VERSION 5.8 ;
BUSBITCHARS "[]" ;
DIVIDERCHAR "/" ;
UNITS
    DATABASE MICRONS 1000 ;
END UNITS

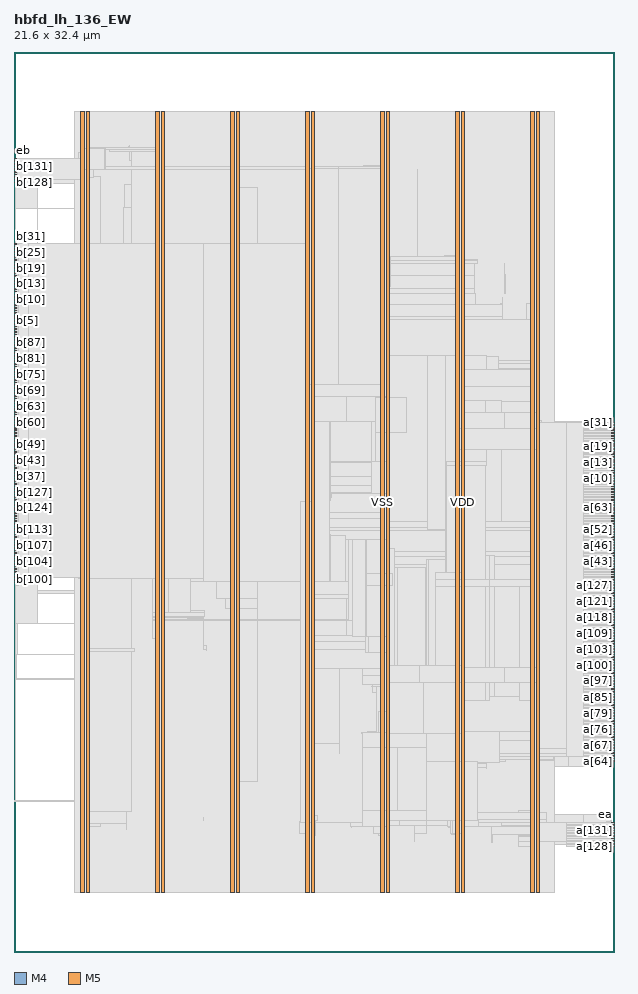
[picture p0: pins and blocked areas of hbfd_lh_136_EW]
MACRO hbfd_lh_136_EW
  FOREIGN hbfd_lh_136_EW 0 0 ;
  CLASS BLOCK ;
  SIZE 21.6 BY 32.4 ;
  PIN a[0]
    DIRECTION INPUT ;
    USE SIGNAL ;
    PORT
      LAYER M4 ;
        RECT  21.516 16.08 21.6 16.104 ;
    END
  END a[0]
  PIN a[100]
    DIRECTION INPUT ;
    USE SIGNAL ;
    PORT
      LAYER M4 ;
        RECT  21.516 10.32 21.6 10.344 ;
    END
  END a[100]
  PIN a[101]
    DIRECTION INPUT ;
    USE SIGNAL ;
    PORT
      LAYER M4 ;
        RECT  21.516 10.416 21.6 10.44 ;
    END
  END a[101]
  PIN a[102]
    DIRECTION INPUT ;
    USE SIGNAL ;
    PORT
      LAYER M4 ;
        RECT  21.516 10.512 21.6 10.536 ;
    END
  END a[102]
  PIN a[103]
    DIRECTION INPUT ;
    USE SIGNAL ;
    PORT
      LAYER M4 ;
        RECT  21.516 10.608 21.6 10.632 ;
    END
  END a[103]
  PIN a[104]
    DIRECTION INPUT ;
    USE SIGNAL ;
    PORT
      LAYER M4 ;
        RECT  21.516 10.704 21.6 10.728 ;
    END
  END a[104]
  PIN a[105]
    DIRECTION INPUT ;
    USE SIGNAL ;
    PORT
      LAYER M4 ;
        RECT  21.516 10.8 21.6 10.824 ;
    END
  END a[105]
  PIN a[106]
    DIRECTION INPUT ;
    USE SIGNAL ;
    PORT
      LAYER M4 ;
        RECT  21.516 10.896 21.6 10.92 ;
    END
  END a[106]
  PIN a[107]
    DIRECTION INPUT ;
    USE SIGNAL ;
    PORT
      LAYER M4 ;
        RECT  21.516 10.992 21.6 11.016 ;
    END
  END a[107]
  PIN a[108]
    DIRECTION INPUT ;
    USE SIGNAL ;
    PORT
      LAYER M4 ;
        RECT  21.516 11.088 21.6 11.112 ;
    END
  END a[108]
  PIN a[109]
    DIRECTION INPUT ;
    USE SIGNAL ;
    PORT
      LAYER M4 ;
        RECT  21.516 11.184 21.6 11.208 ;
    END
  END a[109]
  PIN a[10]
    DIRECTION INPUT ;
    USE SIGNAL ;
    PORT
      LAYER M4 ;
        RECT  21.516 17.04 21.6 17.064 ;
    END
  END a[10]
  PIN a[110]
    DIRECTION INPUT ;
    USE SIGNAL ;
    PORT
      LAYER M4 ;
        RECT  21.516 11.28 21.6 11.304 ;
    END
  END a[110]
  PIN a[111]
    DIRECTION INPUT ;
    USE SIGNAL ;
    PORT
      LAYER M4 ;
        RECT  21.516 11.376 21.6 11.4 ;
    END
  END a[111]
  PIN a[112]
    DIRECTION INPUT ;
    USE SIGNAL ;
    PORT
      LAYER M4 ;
        RECT  21.516 11.472 21.6 11.496 ;
    END
  END a[112]
  PIN a[113]
    DIRECTION INPUT ;
    USE SIGNAL ;
    PORT
      LAYER M4 ;
        RECT  21.516 11.568 21.6 11.592 ;
    END
  END a[113]
  PIN a[114]
    DIRECTION INPUT ;
    USE SIGNAL ;
    PORT
      LAYER M4 ;
        RECT  21.516 11.664 21.6 11.688 ;
    END
  END a[114]
  PIN a[115]
    DIRECTION INPUT ;
    USE SIGNAL ;
    PORT
      LAYER M4 ;
        RECT  21.516 11.76 21.6 11.784 ;
    END
  END a[115]
  PIN a[116]
    DIRECTION INPUT ;
    USE SIGNAL ;
    PORT
      LAYER M4 ;
        RECT  21.516 11.856 21.6 11.88 ;
    END
  END a[116]
  PIN a[117]
    DIRECTION INPUT ;
    USE SIGNAL ;
    PORT
      LAYER M4 ;
        RECT  21.516 11.952 21.6 11.976 ;
    END
  END a[117]
  PIN a[118]
    DIRECTION INPUT ;
    USE SIGNAL ;
    PORT
      LAYER M4 ;
        RECT  21.516 12.048 21.6 12.072 ;
    END
  END a[118]
  PIN a[119]
    DIRECTION INPUT ;
    USE SIGNAL ;
    PORT
      LAYER M4 ;
        RECT  21.516 12.144 21.6 12.168 ;
    END
  END a[119]
  PIN a[11]
    DIRECTION INPUT ;
    USE SIGNAL ;
    PORT
      LAYER M4 ;
        RECT  21.516 17.136 21.6 17.16 ;
    END
  END a[11]
  PIN a[120]
    DIRECTION INPUT ;
    USE SIGNAL ;
    PORT
      LAYER M4 ;
        RECT  21.516 12.24 21.6 12.264 ;
    END
  END a[120]
  PIN a[121]
    DIRECTION INPUT ;
    USE SIGNAL ;
    PORT
      LAYER M4 ;
        RECT  21.516 12.336 21.6 12.36 ;
    END
  END a[121]
  PIN a[122]
    DIRECTION INPUT ;
    USE SIGNAL ;
    PORT
      LAYER M4 ;
        RECT  21.516 12.432 21.6 12.456 ;
    END
  END a[122]
  PIN a[123]
    DIRECTION INPUT ;
    USE SIGNAL ;
    PORT
      LAYER M4 ;
        RECT  21.516 12.528 21.6 12.552 ;
    END
  END a[123]
  PIN a[124]
    DIRECTION INPUT ;
    USE SIGNAL ;
    PORT
      LAYER M4 ;
        RECT  21.516 12.624 21.6 12.648 ;
    END
  END a[124]
  PIN a[125]
    DIRECTION INPUT ;
    USE SIGNAL ;
    PORT
      LAYER M4 ;
        RECT  21.516 12.72 21.6 12.744 ;
    END
  END a[125]
  PIN a[126]
    DIRECTION INPUT ;
    USE SIGNAL ;
    PORT
      LAYER M4 ;
        RECT  21.516 12.816 21.6 12.84 ;
    END
  END a[126]
  PIN a[127]
    DIRECTION INPUT ;
    USE SIGNAL ;
    PORT
      LAYER M4 ;
        RECT  21.516 12.912 21.6 12.936 ;
    END
  END a[127]
  PIN a[128]
    DIRECTION INPUT ;
    USE SIGNAL ;
    PORT
      LAYER M4 ;
        RECT  21.516 3.792 21.6 3.816 ;
    END
  END a[128]
  PIN a[129]
    DIRECTION INPUT ;
    USE SIGNAL ;
    PORT
      LAYER M4 ;
        RECT  21.516 3.888 21.6 3.912 ;
    END
  END a[129]
  PIN a[12]
    DIRECTION INPUT ;
    USE SIGNAL ;
    PORT
      LAYER M4 ;
        RECT  21.516 17.232 21.6 17.256 ;
    END
  END a[12]
  PIN a[130]
    DIRECTION INPUT ;
    USE SIGNAL ;
    PORT
      LAYER M4 ;
        RECT  21.516 3.984 21.6 4.008 ;
    END
  END a[130]
  PIN a[131]
    DIRECTION INPUT ;
    USE SIGNAL ;
    PORT
      LAYER M4 ;
        RECT  21.516 4.08 21.6 4.104 ;
    END
  END a[131]
  PIN a[132]
    DIRECTION INPUT ;
    USE SIGNAL ;
    PORT
      LAYER M4 ;
        RECT  21.516 4.176 21.6 4.2 ;
    END
  END a[132]
  PIN a[133]
    DIRECTION INPUT ;
    USE SIGNAL ;
    PORT
      LAYER M4 ;
        RECT  21.516 4.272 21.6 4.296 ;
    END
  END a[133]
  PIN a[134]
    DIRECTION INPUT ;
    USE SIGNAL ;
    PORT
      LAYER M4 ;
        RECT  21.516 4.368 21.6 4.392 ;
    END
  END a[134]
  PIN a[135]
    DIRECTION INPUT ;
    USE SIGNAL ;
    PORT
      LAYER M4 ;
        RECT  21.516 4.464 21.6 4.488 ;
    END
  END a[135]
  PIN a[13]
    DIRECTION INPUT ;
    USE SIGNAL ;
    PORT
      LAYER M4 ;
        RECT  21.516 17.328 21.6 17.352 ;
    END
  END a[13]
  PIN a[14]
    DIRECTION INPUT ;
    USE SIGNAL ;
    PORT
      LAYER M4 ;
        RECT  21.516 17.424 21.6 17.448 ;
    END
  END a[14]
  PIN a[15]
    DIRECTION INPUT ;
    USE SIGNAL ;
    PORT
      LAYER M4 ;
        RECT  21.516 17.52 21.6 17.544 ;
    END
  END a[15]
  PIN a[16]
    DIRECTION INPUT ;
    USE SIGNAL ;
    PORT
      LAYER M4 ;
        RECT  21.516 17.616 21.6 17.64 ;
    END
  END a[16]
  PIN a[17]
    DIRECTION INPUT ;
    USE SIGNAL ;
    PORT
      LAYER M4 ;
        RECT  21.516 17.712 21.6 17.736 ;
    END
  END a[17]
  PIN a[18]
    DIRECTION INPUT ;
    USE SIGNAL ;
    PORT
      LAYER M4 ;
        RECT  21.516 17.808 21.6 17.832 ;
    END
  END a[18]
  PIN a[19]
    DIRECTION INPUT ;
    USE SIGNAL ;
    PORT
      LAYER M4 ;
        RECT  21.516 17.904 21.6 17.928 ;
    END
  END a[19]
  PIN a[1]
    DIRECTION INPUT ;
    USE SIGNAL ;
    PORT
      LAYER M4 ;
        RECT  21.516 16.176 21.6 16.2 ;
    END
  END a[1]
  PIN a[20]
    DIRECTION INPUT ;
    USE SIGNAL ;
    PORT
      LAYER M4 ;
        RECT  21.516 18 21.6 18.024 ;
    END
  END a[20]
  PIN a[21]
    DIRECTION INPUT ;
    USE SIGNAL ;
    PORT
      LAYER M4 ;
        RECT  21.516 18.096 21.6 18.12 ;
    END
  END a[21]
  PIN a[22]
    DIRECTION INPUT ;
    USE SIGNAL ;
    PORT
      LAYER M4 ;
        RECT  21.516 18.192 21.6 18.216 ;
    END
  END a[22]
  PIN a[23]
    DIRECTION INPUT ;
    USE SIGNAL ;
    PORT
      LAYER M4 ;
        RECT  21.516 18.288 21.6 18.312 ;
    END
  END a[23]
  PIN a[24]
    DIRECTION INPUT ;
    USE SIGNAL ;
    PORT
      LAYER M4 ;
        RECT  21.516 18.384 21.6 18.408 ;
    END
  END a[24]
  PIN a[25]
    DIRECTION INPUT ;
    USE SIGNAL ;
    PORT
      LAYER M4 ;
        RECT  21.516 18.48 21.6 18.504 ;
    END
  END a[25]
  PIN a[26]
    DIRECTION INPUT ;
    USE SIGNAL ;
    PORT
      LAYER M4 ;
        RECT  21.516 18.576 21.6 18.6 ;
    END
  END a[26]
  PIN a[27]
    DIRECTION INPUT ;
    USE SIGNAL ;
    PORT
      LAYER M4 ;
        RECT  21.516 18.672 21.6 18.696 ;
    END
  END a[27]
  PIN a[28]
    DIRECTION INPUT ;
    USE SIGNAL ;
    PORT
      LAYER M4 ;
        RECT  21.516 18.768 21.6 18.792 ;
    END
  END a[28]
  PIN a[29]
    DIRECTION INPUT ;
    USE SIGNAL ;
    PORT
      LAYER M4 ;
        RECT  21.516 18.864 21.6 18.888 ;
    END
  END a[29]
  PIN a[2]
    DIRECTION INPUT ;
    USE SIGNAL ;
    PORT
      LAYER M4 ;
        RECT  21.516 16.272 21.6 16.296 ;
    END
  END a[2]
  PIN a[30]
    DIRECTION INPUT ;
    USE SIGNAL ;
    PORT
      LAYER M4 ;
        RECT  21.516 18.96 21.6 18.984 ;
    END
  END a[30]
  PIN a[31]
    DIRECTION INPUT ;
    USE SIGNAL ;
    PORT
      LAYER M4 ;
        RECT  21.516 19.056 21.6 19.08 ;
    END
  END a[31]
  PIN a[32]
    DIRECTION INPUT ;
    USE SIGNAL ;
    PORT
      LAYER M4 ;
        RECT  21.516 13.008 21.6 13.032 ;
    END
  END a[32]
  PIN a[33]
    DIRECTION INPUT ;
    USE SIGNAL ;
    PORT
      LAYER M4 ;
        RECT  21.516 13.104 21.6 13.128 ;
    END
  END a[33]
  PIN a[34]
    DIRECTION INPUT ;
    USE SIGNAL ;
    PORT
      LAYER M4 ;
        RECT  21.516 13.2 21.6 13.224 ;
    END
  END a[34]
  PIN a[35]
    DIRECTION INPUT ;
    USE SIGNAL ;
    PORT
      LAYER M4 ;
        RECT  21.516 13.296 21.6 13.32 ;
    END
  END a[35]
  PIN a[36]
    DIRECTION INPUT ;
    USE SIGNAL ;
    PORT
      LAYER M4 ;
        RECT  21.516 13.392 21.6 13.416 ;
    END
  END a[36]
  PIN a[37]
    DIRECTION INPUT ;
    USE SIGNAL ;
    PORT
      LAYER M4 ;
        RECT  21.516 13.488 21.6 13.512 ;
    END
  END a[37]
  PIN a[38]
    DIRECTION INPUT ;
    USE SIGNAL ;
    PORT
      LAYER M4 ;
        RECT  21.516 13.584 21.6 13.608 ;
    END
  END a[38]
  PIN a[39]
    DIRECTION INPUT ;
    USE SIGNAL ;
    PORT
      LAYER M4 ;
        RECT  21.516 13.68 21.6 13.704 ;
    END
  END a[39]
  PIN a[3]
    DIRECTION INPUT ;
    USE SIGNAL ;
    PORT
      LAYER M4 ;
        RECT  21.516 16.368 21.6 16.392 ;
    END
  END a[3]
  PIN a[40]
    DIRECTION INPUT ;
    USE SIGNAL ;
    PORT
      LAYER M4 ;
        RECT  21.516 13.776 21.6 13.8 ;
    END
  END a[40]
  PIN a[41]
    DIRECTION INPUT ;
    USE SIGNAL ;
    PORT
      LAYER M4 ;
        RECT  21.516 13.872 21.6 13.896 ;
    END
  END a[41]
  PIN a[42]
    DIRECTION INPUT ;
    USE SIGNAL ;
    PORT
      LAYER M4 ;
        RECT  21.516 13.968 21.6 13.992 ;
    END
  END a[42]
  PIN a[43]
    DIRECTION INPUT ;
    USE SIGNAL ;
    PORT
      LAYER M4 ;
        RECT  21.516 14.064 21.6 14.088 ;
    END
  END a[43]
  PIN a[44]
    DIRECTION INPUT ;
    USE SIGNAL ;
    PORT
      LAYER M4 ;
        RECT  21.516 14.16 21.6 14.184 ;
    END
  END a[44]
  PIN a[45]
    DIRECTION INPUT ;
    USE SIGNAL ;
    PORT
      LAYER M4 ;
        RECT  21.516 14.256 21.6 14.28 ;
    END
  END a[45]
  PIN a[46]
    DIRECTION INPUT ;
    USE SIGNAL ;
    PORT
      LAYER M4 ;
        RECT  21.516 14.352 21.6 14.376 ;
    END
  END a[46]
  PIN a[47]
    DIRECTION INPUT ;
    USE SIGNAL ;
    PORT
      LAYER M4 ;
        RECT  21.516 14.448 21.6 14.472 ;
    END
  END a[47]
  PIN a[48]
    DIRECTION INPUT ;
    USE SIGNAL ;
    PORT
      LAYER M4 ;
        RECT  21.516 14.544 21.6 14.568 ;
    END
  END a[48]
  PIN a[49]
    DIRECTION INPUT ;
    USE SIGNAL ;
    PORT
      LAYER M4 ;
        RECT  21.516 14.64 21.6 14.664 ;
    END
  END a[49]
  PIN a[4]
    DIRECTION INPUT ;
    USE SIGNAL ;
    PORT
      LAYER M4 ;
        RECT  21.516 16.464 21.6 16.488 ;
    END
  END a[4]
  PIN a[50]
    DIRECTION INPUT ;
    USE SIGNAL ;
    PORT
      LAYER M4 ;
        RECT  21.516 14.736 21.6 14.76 ;
    END
  END a[50]
  PIN a[51]
    DIRECTION INPUT ;
    USE SIGNAL ;
    PORT
      LAYER M4 ;
        RECT  21.516 14.832 21.6 14.856 ;
    END
  END a[51]
  PIN a[52]
    DIRECTION INPUT ;
    USE SIGNAL ;
    PORT
      LAYER M4 ;
        RECT  21.516 14.928 21.6 14.952 ;
    END
  END a[52]
  PIN a[53]
    DIRECTION INPUT ;
    USE SIGNAL ;
    PORT
      LAYER M4 ;
        RECT  21.516 15.024 21.6 15.048 ;
    END
  END a[53]
  PIN a[54]
    DIRECTION INPUT ;
    USE SIGNAL ;
    PORT
      LAYER M4 ;
        RECT  21.516 15.12 21.6 15.144 ;
    END
  END a[54]
  PIN a[55]
    DIRECTION INPUT ;
    USE SIGNAL ;
    PORT
      LAYER M4 ;
        RECT  21.516 15.216 21.6 15.24 ;
    END
  END a[55]
  PIN a[56]
    DIRECTION INPUT ;
    USE SIGNAL ;
    PORT
      LAYER M4 ;
        RECT  21.516 15.312 21.6 15.336 ;
    END
  END a[56]
  PIN a[57]
    DIRECTION INPUT ;
    USE SIGNAL ;
    PORT
      LAYER M4 ;
        RECT  21.516 15.408 21.6 15.432 ;
    END
  END a[57]
  PIN a[58]
    DIRECTION INPUT ;
    USE SIGNAL ;
    PORT
      LAYER M4 ;
        RECT  21.516 15.504 21.6 15.528 ;
    END
  END a[58]
  PIN a[59]
    DIRECTION INPUT ;
    USE SIGNAL ;
    PORT
      LAYER M4 ;
        RECT  21.516 15.6 21.6 15.624 ;
    END
  END a[59]
  PIN a[5]
    DIRECTION INPUT ;
    USE SIGNAL ;
    PORT
      LAYER M4 ;
        RECT  21.516 16.56 21.6 16.584 ;
    END
  END a[5]
  PIN a[60]
    DIRECTION INPUT ;
    USE SIGNAL ;
    PORT
      LAYER M4 ;
        RECT  21.516 15.696 21.6 15.72 ;
    END
  END a[60]
  PIN a[61]
    DIRECTION INPUT ;
    USE SIGNAL ;
    PORT
      LAYER M4 ;
        RECT  21.516 15.792 21.6 15.816 ;
    END
  END a[61]
  PIN a[62]
    DIRECTION INPUT ;
    USE SIGNAL ;
    PORT
      LAYER M4 ;
        RECT  21.516 15.888 21.6 15.912 ;
    END
  END a[62]
  PIN a[63]
    DIRECTION INPUT ;
    USE SIGNAL ;
    PORT
      LAYER M4 ;
        RECT  21.516 15.984 21.6 16.008 ;
    END
  END a[63]
  PIN a[64]
    DIRECTION INPUT ;
    USE SIGNAL ;
    PORT
      LAYER M4 ;
        RECT  21.516 6.864 21.6 6.888 ;
    END
  END a[64]
  PIN a[65]
    DIRECTION INPUT ;
    USE SIGNAL ;
    PORT
      LAYER M4 ;
        RECT  21.516 6.96 21.6 6.984 ;
    END
  END a[65]
  PIN a[66]
    DIRECTION INPUT ;
    USE SIGNAL ;
    PORT
      LAYER M4 ;
        RECT  21.516 7.056 21.6 7.08 ;
    END
  END a[66]
  PIN a[67]
    DIRECTION INPUT ;
    USE SIGNAL ;
    PORT
      LAYER M4 ;
        RECT  21.516 7.152 21.6 7.176 ;
    END
  END a[67]
  PIN a[68]
    DIRECTION INPUT ;
    USE SIGNAL ;
    PORT
      LAYER M4 ;
        RECT  21.516 7.248 21.6 7.272 ;
    END
  END a[68]
  PIN a[69]
    DIRECTION INPUT ;
    USE SIGNAL ;
    PORT
      LAYER M4 ;
        RECT  21.516 7.344 21.6 7.368 ;
    END
  END a[69]
  PIN a[6]
    DIRECTION INPUT ;
    USE SIGNAL ;
    PORT
      LAYER M4 ;
        RECT  21.516 16.656 21.6 16.68 ;
    END
  END a[6]
  PIN a[70]
    DIRECTION INPUT ;
    USE SIGNAL ;
    PORT
      LAYER M4 ;
        RECT  21.516 7.44 21.6 7.464 ;
    END
  END a[70]
  PIN a[71]
    DIRECTION INPUT ;
    USE SIGNAL ;
    PORT
      LAYER M4 ;
        RECT  21.516 7.536 21.6 7.56 ;
    END
  END a[71]
  PIN a[72]
    DIRECTION INPUT ;
    USE SIGNAL ;
    PORT
      LAYER M4 ;
        RECT  21.516 7.632 21.6 7.656 ;
    END
  END a[72]
  PIN a[73]
    DIRECTION INPUT ;
    USE SIGNAL ;
    PORT
      LAYER M4 ;
        RECT  21.516 7.728 21.6 7.752 ;
    END
  END a[73]
  PIN a[74]
    DIRECTION INPUT ;
    USE SIGNAL ;
    PORT
      LAYER M4 ;
        RECT  21.516 7.824 21.6 7.848 ;
    END
  END a[74]
  PIN a[75]
    DIRECTION INPUT ;
    USE SIGNAL ;
    PORT
      LAYER M4 ;
        RECT  21.516 7.92 21.6 7.944 ;
    END
  END a[75]
  PIN a[76]
    DIRECTION INPUT ;
    USE SIGNAL ;
    PORT
      LAYER M4 ;
        RECT  21.516 8.016 21.6 8.04 ;
    END
  END a[76]
  PIN a[77]
    DIRECTION INPUT ;
    USE SIGNAL ;
    PORT
      LAYER M4 ;
        RECT  21.516 8.112 21.6 8.136 ;
    END
  END a[77]
  PIN a[78]
    DIRECTION INPUT ;
    USE SIGNAL ;
    PORT
      LAYER M4 ;
        RECT  21.516 8.208 21.6 8.232 ;
    END
  END a[78]
  PIN a[79]
    DIRECTION INPUT ;
    USE SIGNAL ;
    PORT
      LAYER M4 ;
        RECT  21.516 8.304 21.6 8.328 ;
    END
  END a[79]
  PIN a[7]
    DIRECTION INPUT ;
    USE SIGNAL ;
    PORT
      LAYER M4 ;
        RECT  21.516 16.752 21.6 16.776 ;
    END
  END a[7]
  PIN a[80]
    DIRECTION INPUT ;
    USE SIGNAL ;
    PORT
      LAYER M4 ;
        RECT  21.516 8.4 21.6 8.424 ;
    END
  END a[80]
  PIN a[81]
    DIRECTION INPUT ;
    USE SIGNAL ;
    PORT
      LAYER M4 ;
        RECT  21.516 8.496 21.6 8.52 ;
    END
  END a[81]
  PIN a[82]
    DIRECTION INPUT ;
    USE SIGNAL ;
    PORT
      LAYER M4 ;
        RECT  21.516 8.592 21.6 8.616 ;
    END
  END a[82]
  PIN a[83]
    DIRECTION INPUT ;
    USE SIGNAL ;
    PORT
      LAYER M4 ;
        RECT  21.516 8.688 21.6 8.712 ;
    END
  END a[83]
  PIN a[84]
    DIRECTION INPUT ;
    USE SIGNAL ;
    PORT
      LAYER M4 ;
        RECT  21.516 8.784 21.6 8.808 ;
    END
  END a[84]
  PIN a[85]
    DIRECTION INPUT ;
    USE SIGNAL ;
    PORT
      LAYER M4 ;
        RECT  21.516 8.88 21.6 8.904 ;
    END
  END a[85]
  PIN a[86]
    DIRECTION INPUT ;
    USE SIGNAL ;
    PORT
      LAYER M4 ;
        RECT  21.516 8.976 21.6 9 ;
    END
  END a[86]
  PIN a[87]
    DIRECTION INPUT ;
    USE SIGNAL ;
    PORT
      LAYER M4 ;
        RECT  21.516 9.072 21.6 9.096 ;
    END
  END a[87]
  PIN a[88]
    DIRECTION INPUT ;
    USE SIGNAL ;
    PORT
      LAYER M4 ;
        RECT  21.516 9.168 21.6 9.192 ;
    END
  END a[88]
  PIN a[89]
    DIRECTION INPUT ;
    USE SIGNAL ;
    PORT
      LAYER M4 ;
        RECT  21.516 9.264 21.6 9.288 ;
    END
  END a[89]
  PIN a[8]
    DIRECTION INPUT ;
    USE SIGNAL ;
    PORT
      LAYER M4 ;
        RECT  21.516 16.848 21.6 16.872 ;
    END
  END a[8]
  PIN a[90]
    DIRECTION INPUT ;
    USE SIGNAL ;
    PORT
      LAYER M4 ;
        RECT  21.516 9.36 21.6 9.384 ;
    END
  END a[90]
  PIN a[91]
    DIRECTION INPUT ;
    USE SIGNAL ;
    PORT
      LAYER M4 ;
        RECT  21.516 9.456 21.6 9.48 ;
    END
  END a[91]
  PIN a[92]
    DIRECTION INPUT ;
    USE SIGNAL ;
    PORT
      LAYER M4 ;
        RECT  21.516 9.552 21.6 9.576 ;
    END
  END a[92]
  PIN a[93]
    DIRECTION INPUT ;
    USE SIGNAL ;
    PORT
      LAYER M4 ;
        RECT  21.516 9.648 21.6 9.672 ;
    END
  END a[93]
  PIN a[94]
    DIRECTION INPUT ;
    USE SIGNAL ;
    PORT
      LAYER M4 ;
        RECT  21.516 9.744 21.6 9.768 ;
    END
  END a[94]
  PIN a[95]
    DIRECTION INPUT ;
    USE SIGNAL ;
    PORT
      LAYER M4 ;
        RECT  21.516 9.84 21.6 9.864 ;
    END
  END a[95]
  PIN a[96]
    DIRECTION INPUT ;
    USE SIGNAL ;
    PORT
      LAYER M4 ;
        RECT  21.516 9.936 21.6 9.96 ;
    END
  END a[96]
  PIN a[97]
    DIRECTION INPUT ;
    USE SIGNAL ;
    PORT
      LAYER M4 ;
        RECT  21.516 10.032 21.6 10.056 ;
    END
  END a[97]
  PIN a[98]
    DIRECTION INPUT ;
    USE SIGNAL ;
    PORT
      LAYER M4 ;
        RECT  21.516 10.128 21.6 10.152 ;
    END
  END a[98]
  PIN a[99]
    DIRECTION INPUT ;
    USE SIGNAL ;
    PORT
      LAYER M4 ;
        RECT  21.516 10.224 21.6 10.248 ;
    END
  END a[99]
  PIN a[9]
    DIRECTION INPUT ;
    USE SIGNAL ;
    PORT
      LAYER M4 ;
        RECT  21.516 16.944 21.6 16.968 ;
    END
  END a[9]
  PIN b[0]
    DIRECTION OUTPUT ;
    USE SIGNAL ;
    PORT
      LAYER M4 ;
        RECT  0 22.512 0.084 22.536 ;
    END
  END b[0]
  PIN b[100]
    DIRECTION OUTPUT ;
    USE SIGNAL ;
    PORT
      LAYER M4 ;
        RECT  0 13.68 0.084 13.704 ;
    END
  END b[100]
  PIN b[101]
    DIRECTION OUTPUT ;
    USE SIGNAL ;
    PORT
      LAYER M4 ;
        RECT  0 13.776 0.084 13.8 ;
    END
  END b[101]
  PIN b[102]
    DIRECTION OUTPUT ;
    USE SIGNAL ;
    PORT
      LAYER M4 ;
        RECT  0 13.872 0.084 13.896 ;
    END
  END b[102]
  PIN b[103]
    DIRECTION OUTPUT ;
    USE SIGNAL ;
    PORT
      LAYER M4 ;
        RECT  0 13.968 0.084 13.992 ;
    END
  END b[103]
  PIN b[104]
    DIRECTION OUTPUT ;
    USE SIGNAL ;
    PORT
      LAYER M4 ;
        RECT  0 14.064 0.084 14.088 ;
    END
  END b[104]
  PIN b[105]
    DIRECTION OUTPUT ;
    USE SIGNAL ;
    PORT
      LAYER M4 ;
        RECT  0 14.16 0.084 14.184 ;
    END
  END b[105]
  PIN b[106]
    DIRECTION OUTPUT ;
    USE SIGNAL ;
    PORT
      LAYER M4 ;
        RECT  0 14.256 0.084 14.28 ;
    END
  END b[106]
  PIN b[107]
    DIRECTION OUTPUT ;
    USE SIGNAL ;
    PORT
      LAYER M4 ;
        RECT  0 14.352 0.084 14.376 ;
    END
  END b[107]
  PIN b[108]
    DIRECTION OUTPUT ;
    USE SIGNAL ;
    PORT
      LAYER M4 ;
        RECT  0 14.448 0.084 14.472 ;
    END
  END b[108]
  PIN b[109]
    DIRECTION OUTPUT ;
    USE SIGNAL ;
    PORT
      LAYER M4 ;
        RECT  0 14.544 0.084 14.568 ;
    END
  END b[109]
  PIN b[10]
    DIRECTION OUTPUT ;
    USE SIGNAL ;
    PORT
      LAYER M4 ;
        RECT  0 23.472 0.084 23.496 ;
    END
  END b[10]
  PIN b[110]
    DIRECTION OUTPUT ;
    USE SIGNAL ;
    PORT
      LAYER M4 ;
        RECT  0 14.64 0.084 14.664 ;
    END
  END b[110]
  PIN b[111]
    DIRECTION OUTPUT ;
    USE SIGNAL ;
    PORT
      LAYER M4 ;
        RECT  0 14.736 0.084 14.76 ;
    END
  END b[111]
  PIN b[112]
    DIRECTION OUTPUT ;
    USE SIGNAL ;
    PORT
      LAYER M4 ;
        RECT  0 14.832 0.084 14.856 ;
    END
  END b[112]
  PIN b[113]
    DIRECTION OUTPUT ;
    USE SIGNAL ;
    PORT
      LAYER M4 ;
        RECT  0 14.928 0.084 14.952 ;
    END
  END b[113]
  PIN b[114]
    DIRECTION OUTPUT ;
    USE SIGNAL ;
    PORT
      LAYER M4 ;
        RECT  0 15.024 0.084 15.048 ;
    END
  END b[114]
  PIN b[115]
    DIRECTION OUTPUT ;
    USE SIGNAL ;
    PORT
      LAYER M4 ;
        RECT  0 15.12 0.084 15.144 ;
    END
  END b[115]
  PIN b[116]
    DIRECTION OUTPUT ;
    USE SIGNAL ;
    PORT
      LAYER M4 ;
        RECT  0 15.216 0.084 15.24 ;
    END
  END b[116]
  PIN b[117]
    DIRECTION OUTPUT ;
    USE SIGNAL ;
    PORT
      LAYER M4 ;
        RECT  0 15.312 0.084 15.336 ;
    END
  END b[117]
  PIN b[118]
    DIRECTION OUTPUT ;
    USE SIGNAL ;
    PORT
      LAYER M4 ;
        RECT  0 15.408 0.084 15.432 ;
    END
  END b[118]
  PIN b[119]
    DIRECTION OUTPUT ;
    USE SIGNAL ;
    PORT
      LAYER M4 ;
        RECT  0 15.504 0.084 15.528 ;
    END
  END b[119]
  PIN b[11]
    DIRECTION OUTPUT ;
    USE SIGNAL ;
    PORT
      LAYER M4 ;
        RECT  0 23.568 0.084 23.592 ;
    END
  END b[11]
  PIN b[120]
    DIRECTION OUTPUT ;
    USE SIGNAL ;
    PORT
      LAYER M4 ;
        RECT  0 15.6 0.084 15.624 ;
    END
  END b[120]
  PIN b[121]
    DIRECTION OUTPUT ;
    USE SIGNAL ;
    PORT
      LAYER M4 ;
        RECT  0 15.696 0.084 15.72 ;
    END
  END b[121]
  PIN b[122]
    DIRECTION OUTPUT ;
    USE SIGNAL ;
    PORT
      LAYER M4 ;
        RECT  0 15.792 0.084 15.816 ;
    END
  END b[122]
  PIN b[123]
    DIRECTION OUTPUT ;
    USE SIGNAL ;
    PORT
      LAYER M4 ;
        RECT  0 15.888 0.084 15.912 ;
    END
  END b[123]
  PIN b[124]
    DIRECTION OUTPUT ;
    USE SIGNAL ;
    PORT
      LAYER M4 ;
        RECT  0 15.984 0.084 16.008 ;
    END
  END b[124]
  PIN b[125]
    DIRECTION OUTPUT ;
    USE SIGNAL ;
    PORT
      LAYER M4 ;
        RECT  0 16.08 0.084 16.104 ;
    END
  END b[125]
  PIN b[126]
    DIRECTION OUTPUT ;
    USE SIGNAL ;
    PORT
      LAYER M4 ;
        RECT  0 16.176 0.084 16.2 ;
    END
  END b[126]
  PIN b[127]
    DIRECTION OUTPUT ;
    USE SIGNAL ;
    PORT
      LAYER M4 ;
        RECT  0 16.272 0.084 16.296 ;
    END
  END b[127]
  PIN b[128]
    DIRECTION OUTPUT ;
    USE SIGNAL ;
    PORT
      LAYER M4 ;
        RECT  0 27.696 0.084 27.72 ;
    END
  END b[128]
  PIN b[129]
    DIRECTION OUTPUT ;
    USE SIGNAL ;
    PORT
      LAYER M4 ;
        RECT  0 27.792 0.084 27.816 ;
    END
  END b[129]
  PIN b[12]
    DIRECTION OUTPUT ;
    USE SIGNAL ;
    PORT
      LAYER M4 ;
        RECT  0 23.664 0.084 23.688 ;
    END
  END b[12]
  PIN b[130]
    DIRECTION OUTPUT ;
    USE SIGNAL ;
    PORT
      LAYER M4 ;
        RECT  0 27.888 0.084 27.912 ;
    END
  END b[130]
  PIN b[131]
    DIRECTION OUTPUT ;
    USE SIGNAL ;
    PORT
      LAYER M4 ;
        RECT  0 27.984 0.084 28.008 ;
    END
  END b[131]
  PIN b[132]
    DIRECTION OUTPUT ;
    USE SIGNAL ;
    PORT
      LAYER M4 ;
        RECT  0 28.08 0.084 28.104 ;
    END
  END b[132]
  PIN b[133]
    DIRECTION OUTPUT ;
    USE SIGNAL ;
    PORT
      LAYER M4 ;
        RECT  0 28.176 0.084 28.2 ;
    END
  END b[133]
  PIN b[134]
    DIRECTION OUTPUT ;
    USE SIGNAL ;
    PORT
      LAYER M4 ;
        RECT  0 28.272 0.084 28.296 ;
    END
  END b[134]
  PIN b[135]
    DIRECTION OUTPUT ;
    USE SIGNAL ;
    PORT
      LAYER M4 ;
        RECT  0 28.368 0.084 28.392 ;
    END
  END b[135]
  PIN b[13]
    DIRECTION OUTPUT ;
    USE SIGNAL ;
    PORT
      LAYER M4 ;
        RECT  0 23.76 0.084 23.784 ;
    END
  END b[13]
  PIN b[14]
    DIRECTION OUTPUT ;
    USE SIGNAL ;
    PORT
      LAYER M4 ;
        RECT  0 23.856 0.084 23.88 ;
    END
  END b[14]
  PIN b[15]
    DIRECTION OUTPUT ;
    USE SIGNAL ;
    PORT
      LAYER M4 ;
        RECT  0 23.952 0.084 23.976 ;
    END
  END b[15]
  PIN b[16]
    DIRECTION OUTPUT ;
    USE SIGNAL ;
    PORT
      LAYER M4 ;
        RECT  0 24.048 0.084 24.072 ;
    END
  END b[16]
  PIN b[17]
    DIRECTION OUTPUT ;
    USE SIGNAL ;
    PORT
      LAYER M4 ;
        RECT  0 24.144 0.084 24.168 ;
    END
  END b[17]
  PIN b[18]
    DIRECTION OUTPUT ;
    USE SIGNAL ;
    PORT
      LAYER M4 ;
        RECT  0 24.24 0.084 24.264 ;
    END
  END b[18]
  PIN b[19]
    DIRECTION OUTPUT ;
    USE SIGNAL ;
    PORT
      LAYER M4 ;
        RECT  0 24.336 0.084 24.36 ;
    END
  END b[19]
  PIN b[1]
    DIRECTION OUTPUT ;
    USE SIGNAL ;
    PORT
      LAYER M4 ;
        RECT  0 22.608 0.084 22.632 ;
    END
  END b[1]
  PIN b[20]
    DIRECTION OUTPUT ;
    USE SIGNAL ;
    PORT
      LAYER M4 ;
        RECT  0 24.432 0.084 24.456 ;
    END
  END b[20]
  PIN b[21]
    DIRECTION OUTPUT ;
    USE SIGNAL ;
    PORT
      LAYER M4 ;
        RECT  0 24.528 0.084 24.552 ;
    END
  END b[21]
  PIN b[22]
    DIRECTION OUTPUT ;
    USE SIGNAL ;
    PORT
      LAYER M4 ;
        RECT  0 24.624 0.084 24.648 ;
    END
  END b[22]
  PIN b[23]
    DIRECTION OUTPUT ;
    USE SIGNAL ;
    PORT
      LAYER M4 ;
        RECT  0 24.72 0.084 24.744 ;
    END
  END b[23]
  PIN b[24]
    DIRECTION OUTPUT ;
    USE SIGNAL ;
    PORT
      LAYER M4 ;
        RECT  0 24.816 0.084 24.84 ;
    END
  END b[24]
  PIN b[25]
    DIRECTION OUTPUT ;
    USE SIGNAL ;
    PORT
      LAYER M4 ;
        RECT  0 24.912 0.084 24.936 ;
    END
  END b[25]
  PIN b[26]
    DIRECTION OUTPUT ;
    USE SIGNAL ;
    PORT
      LAYER M4 ;
        RECT  0 25.008 0.084 25.032 ;
    END
  END b[26]
  PIN b[27]
    DIRECTION OUTPUT ;
    USE SIGNAL ;
    PORT
      LAYER M4 ;
        RECT  0 25.104 0.084 25.128 ;
    END
  END b[27]
  PIN b[28]
    DIRECTION OUTPUT ;
    USE SIGNAL ;
    PORT
      LAYER M4 ;
        RECT  0 25.2 0.084 25.224 ;
    END
  END b[28]
  PIN b[29]
    DIRECTION OUTPUT ;
    USE SIGNAL ;
    PORT
      LAYER M4 ;
        RECT  0 25.296 0.084 25.32 ;
    END
  END b[29]
  PIN b[2]
    DIRECTION OUTPUT ;
    USE SIGNAL ;
    PORT
      LAYER M4 ;
        RECT  0 22.704 0.084 22.728 ;
    END
  END b[2]
  PIN b[30]
    DIRECTION OUTPUT ;
    USE SIGNAL ;
    PORT
      LAYER M4 ;
        RECT  0 25.392 0.084 25.416 ;
    END
  END b[30]
  PIN b[31]
    DIRECTION OUTPUT ;
    USE SIGNAL ;
    PORT
      LAYER M4 ;
        RECT  0 25.488 0.084 25.512 ;
    END
  END b[31]
  PIN b[32]
    DIRECTION OUTPUT ;
    USE SIGNAL ;
    PORT
      LAYER M4 ;
        RECT  0 16.368 0.084 16.392 ;
    END
  END b[32]
  PIN b[33]
    DIRECTION OUTPUT ;
    USE SIGNAL ;
    PORT
      LAYER M4 ;
        RECT  0 16.464 0.084 16.488 ;
    END
  END b[33]
  PIN b[34]
    DIRECTION OUTPUT ;
    USE SIGNAL ;
    PORT
      LAYER M4 ;
        RECT  0 16.56 0.084 16.584 ;
    END
  END b[34]
  PIN b[35]
    DIRECTION OUTPUT ;
    USE SIGNAL ;
    PORT
      LAYER M4 ;
        RECT  0 16.656 0.084 16.68 ;
    END
  END b[35]
  PIN b[36]
    DIRECTION OUTPUT ;
    USE SIGNAL ;
    PORT
      LAYER M4 ;
        RECT  0 16.752 0.084 16.776 ;
    END
  END b[36]
  PIN b[37]
    DIRECTION OUTPUT ;
    USE SIGNAL ;
    PORT
      LAYER M4 ;
        RECT  0 16.848 0.084 16.872 ;
    END
  END b[37]
  PIN b[38]
    DIRECTION OUTPUT ;
    USE SIGNAL ;
    PORT
      LAYER M4 ;
        RECT  0 16.944 0.084 16.968 ;
    END
  END b[38]
  PIN b[39]
    DIRECTION OUTPUT ;
    USE SIGNAL ;
    PORT
      LAYER M4 ;
        RECT  0 17.04 0.084 17.064 ;
    END
  END b[39]
  PIN b[3]
    DIRECTION OUTPUT ;
    USE SIGNAL ;
    PORT
      LAYER M4 ;
        RECT  0 22.8 0.084 22.824 ;
    END
  END b[3]
  PIN b[40]
    DIRECTION OUTPUT ;
    USE SIGNAL ;
    PORT
      LAYER M4 ;
        RECT  0 17.136 0.084 17.16 ;
    END
  END b[40]
  PIN b[41]
    DIRECTION OUTPUT ;
    USE SIGNAL ;
    PORT
      LAYER M4 ;
        RECT  0 17.232 0.084 17.256 ;
    END
  END b[41]
  PIN b[42]
    DIRECTION OUTPUT ;
    USE SIGNAL ;
    PORT
      LAYER M4 ;
        RECT  0 17.328 0.084 17.352 ;
    END
  END b[42]
  PIN b[43]
    DIRECTION OUTPUT ;
    USE SIGNAL ;
    PORT
      LAYER M4 ;
        RECT  0 17.424 0.084 17.448 ;
    END
  END b[43]
  PIN b[44]
    DIRECTION OUTPUT ;
    USE SIGNAL ;
    PORT
      LAYER M4 ;
        RECT  0 17.52 0.084 17.544 ;
    END
  END b[44]
  PIN b[45]
    DIRECTION OUTPUT ;
    USE SIGNAL ;
    PORT
      LAYER M4 ;
        RECT  0 17.616 0.084 17.64 ;
    END
  END b[45]
  PIN b[46]
    DIRECTION OUTPUT ;
    USE SIGNAL ;
    PORT
      LAYER M4 ;
        RECT  0 17.712 0.084 17.736 ;
    END
  END b[46]
  PIN b[47]
    DIRECTION OUTPUT ;
    USE SIGNAL ;
    PORT
      LAYER M4 ;
        RECT  0 17.808 0.084 17.832 ;
    END
  END b[47]
  PIN b[48]
    DIRECTION OUTPUT ;
    USE SIGNAL ;
    PORT
      LAYER M4 ;
        RECT  0 17.904 0.084 17.928 ;
    END
  END b[48]
  PIN b[49]
    DIRECTION OUTPUT ;
    USE SIGNAL ;
    PORT
      LAYER M4 ;
        RECT  0 18 0.084 18.024 ;
    END
  END b[49]
  PIN b[4]
    DIRECTION OUTPUT ;
    USE SIGNAL ;
    PORT
      LAYER M4 ;
        RECT  0 22.896 0.084 22.92 ;
    END
  END b[4]
  PIN b[50]
    DIRECTION OUTPUT ;
    USE SIGNAL ;
    PORT
      LAYER M4 ;
        RECT  0 18.096 0.084 18.12 ;
    END
  END b[50]
  PIN b[51]
    DIRECTION OUTPUT ;
    USE SIGNAL ;
    PORT
      LAYER M4 ;
        RECT  0 18.192 0.084 18.216 ;
    END
  END b[51]
  PIN b[52]
    DIRECTION OUTPUT ;
    USE SIGNAL ;
    PORT
      LAYER M4 ;
        RECT  0 18.288 0.084 18.312 ;
    END
  END b[52]
  PIN b[53]
    DIRECTION OUTPUT ;
    USE SIGNAL ;
    PORT
      LAYER M4 ;
        RECT  0 18.384 0.084 18.408 ;
    END
  END b[53]
  PIN b[54]
    DIRECTION OUTPUT ;
    USE SIGNAL ;
    PORT
      LAYER M4 ;
        RECT  0 18.48 0.084 18.504 ;
    END
  END b[54]
  PIN b[55]
    DIRECTION OUTPUT ;
    USE SIGNAL ;
    PORT
      LAYER M4 ;
        RECT  0 18.576 0.084 18.6 ;
    END
  END b[55]
  PIN b[56]
    DIRECTION OUTPUT ;
    USE SIGNAL ;
    PORT
      LAYER M4 ;
        RECT  0 18.672 0.084 18.696 ;
    END
  END b[56]
  PIN b[57]
    DIRECTION OUTPUT ;
    USE SIGNAL ;
    PORT
      LAYER M4 ;
        RECT  0 18.768 0.084 18.792 ;
    END
  END b[57]
  PIN b[58]
    DIRECTION OUTPUT ;
    USE SIGNAL ;
    PORT
      LAYER M4 ;
        RECT  0 18.864 0.084 18.888 ;
    END
  END b[58]
  PIN b[59]
    DIRECTION OUTPUT ;
    USE SIGNAL ;
    PORT
      LAYER M4 ;
        RECT  0 18.96 0.084 18.984 ;
    END
  END b[59]
  PIN b[5]
    DIRECTION OUTPUT ;
    USE SIGNAL ;
    PORT
      LAYER M4 ;
        RECT  0 22.992 0.084 23.016 ;
    END
  END b[5]
  PIN b[60]
    DIRECTION OUTPUT ;
    USE SIGNAL ;
    PORT
      LAYER M4 ;
        RECT  0 19.056 0.084 19.08 ;
    END
  END b[60]
  PIN b[61]
    DIRECTION OUTPUT ;
    USE SIGNAL ;
    PORT
      LAYER M4 ;
        RECT  0 19.152 0.084 19.176 ;
    END
  END b[61]
  PIN b[62]
    DIRECTION OUTPUT ;
    USE SIGNAL ;
    PORT
      LAYER M4 ;
        RECT  0 19.248 0.084 19.272 ;
    END
  END b[62]
  PIN b[63]
    DIRECTION OUTPUT ;
    USE SIGNAL ;
    PORT
      LAYER M4 ;
        RECT  0 19.344 0.084 19.368 ;
    END
  END b[63]
  PIN b[64]
    DIRECTION OUTPUT ;
    USE SIGNAL ;
    PORT
      LAYER M4 ;
        RECT  0 19.44 0.084 19.464 ;
    END
  END b[64]
  PIN b[65]
    DIRECTION OUTPUT ;
    USE SIGNAL ;
    PORT
      LAYER M4 ;
        RECT  0 19.536 0.084 19.56 ;
    END
  END b[65]
  PIN b[66]
    DIRECTION OUTPUT ;
    USE SIGNAL ;
    PORT
      LAYER M4 ;
        RECT  0 19.632 0.084 19.656 ;
    END
  END b[66]
  PIN b[67]
    DIRECTION OUTPUT ;
    USE SIGNAL ;
    PORT
      LAYER M4 ;
        RECT  0 19.728 0.084 19.752 ;
    END
  END b[67]
  PIN b[68]
    DIRECTION OUTPUT ;
    USE SIGNAL ;
    PORT
      LAYER M4 ;
        RECT  0 19.824 0.084 19.848 ;
    END
  END b[68]
  PIN b[69]
    DIRECTION OUTPUT ;
    USE SIGNAL ;
    PORT
      LAYER M4 ;
        RECT  0 19.92 0.084 19.944 ;
    END
  END b[69]
  PIN b[6]
    DIRECTION OUTPUT ;
    USE SIGNAL ;
    PORT
      LAYER M4 ;
        RECT  0 23.088 0.084 23.112 ;
    END
  END b[6]
  PIN b[70]
    DIRECTION OUTPUT ;
    USE SIGNAL ;
    PORT
      LAYER M4 ;
        RECT  0 20.016 0.084 20.04 ;
    END
  END b[70]
  PIN b[71]
    DIRECTION OUTPUT ;
    USE SIGNAL ;
    PORT
      LAYER M4 ;
        RECT  0 20.112 0.084 20.136 ;
    END
  END b[71]
  PIN b[72]
    DIRECTION OUTPUT ;
    USE SIGNAL ;
    PORT
      LAYER M4 ;
        RECT  0 20.208 0.084 20.232 ;
    END
  END b[72]
  PIN b[73]
    DIRECTION OUTPUT ;
    USE SIGNAL ;
    PORT
      LAYER M4 ;
        RECT  0 20.304 0.084 20.328 ;
    END
  END b[73]
  PIN b[74]
    DIRECTION OUTPUT ;
    USE SIGNAL ;
    PORT
      LAYER M4 ;
        RECT  0 20.4 0.084 20.424 ;
    END
  END b[74]
  PIN b[75]
    DIRECTION OUTPUT ;
    USE SIGNAL ;
    PORT
      LAYER M4 ;
        RECT  0 20.496 0.084 20.52 ;
    END
  END b[75]
  PIN b[76]
    DIRECTION OUTPUT ;
    USE SIGNAL ;
    PORT
      LAYER M4 ;
        RECT  0 20.592 0.084 20.616 ;
    END
  END b[76]
  PIN b[77]
    DIRECTION OUTPUT ;
    USE SIGNAL ;
    PORT
      LAYER M4 ;
        RECT  0 20.688 0.084 20.712 ;
    END
  END b[77]
  PIN b[78]
    DIRECTION OUTPUT ;
    USE SIGNAL ;
    PORT
      LAYER M4 ;
        RECT  0 20.784 0.084 20.808 ;
    END
  END b[78]
  PIN b[79]
    DIRECTION OUTPUT ;
    USE SIGNAL ;
    PORT
      LAYER M4 ;
        RECT  0 20.88 0.084 20.904 ;
    END
  END b[79]
  PIN b[7]
    DIRECTION OUTPUT ;
    USE SIGNAL ;
    PORT
      LAYER M4 ;
        RECT  0 23.184 0.084 23.208 ;
    END
  END b[7]
  PIN b[80]
    DIRECTION OUTPUT ;
    USE SIGNAL ;
    PORT
      LAYER M4 ;
        RECT  0 20.976 0.084 21 ;
    END
  END b[80]
  PIN b[81]
    DIRECTION OUTPUT ;
    USE SIGNAL ;
    PORT
      LAYER M4 ;
        RECT  0 21.072 0.084 21.096 ;
    END
  END b[81]
  PIN b[82]
    DIRECTION OUTPUT ;
    USE SIGNAL ;
    PORT
      LAYER M4 ;
        RECT  0 21.168 0.084 21.192 ;
    END
  END b[82]
  PIN b[83]
    DIRECTION OUTPUT ;
    USE SIGNAL ;
    PORT
      LAYER M4 ;
        RECT  0 21.264 0.084 21.288 ;
    END
  END b[83]
  PIN b[84]
    DIRECTION OUTPUT ;
    USE SIGNAL ;
    PORT
      LAYER M4 ;
        RECT  0 21.36 0.084 21.384 ;
    END
  END b[84]
  PIN b[85]
    DIRECTION OUTPUT ;
    USE SIGNAL ;
    PORT
      LAYER M4 ;
        RECT  0 21.456 0.084 21.48 ;
    END
  END b[85]
  PIN b[86]
    DIRECTION OUTPUT ;
    USE SIGNAL ;
    PORT
      LAYER M4 ;
        RECT  0 21.552 0.084 21.576 ;
    END
  END b[86]
  PIN b[87]
    DIRECTION OUTPUT ;
    USE SIGNAL ;
    PORT
      LAYER M4 ;
        RECT  0 21.648 0.084 21.672 ;
    END
  END b[87]
  PIN b[88]
    DIRECTION OUTPUT ;
    USE SIGNAL ;
    PORT
      LAYER M4 ;
        RECT  0 21.744 0.084 21.768 ;
    END
  END b[88]
  PIN b[89]
    DIRECTION OUTPUT ;
    USE SIGNAL ;
    PORT
      LAYER M4 ;
        RECT  0 21.84 0.084 21.864 ;
    END
  END b[89]
  PIN b[8]
    DIRECTION OUTPUT ;
    USE SIGNAL ;
    PORT
      LAYER M4 ;
        RECT  0 23.28 0.084 23.304 ;
    END
  END b[8]
  PIN b[90]
    DIRECTION OUTPUT ;
    USE SIGNAL ;
    PORT
      LAYER M4 ;
        RECT  0 21.936 0.084 21.96 ;
    END
  END b[90]
  PIN b[91]
    DIRECTION OUTPUT ;
    USE SIGNAL ;
    PORT
      LAYER M4 ;
        RECT  0 22.032 0.084 22.056 ;
    END
  END b[91]
  PIN b[92]
    DIRECTION OUTPUT ;
    USE SIGNAL ;
    PORT
      LAYER M4 ;
        RECT  0 22.128 0.084 22.152 ;
    END
  END b[92]
  PIN b[93]
    DIRECTION OUTPUT ;
    USE SIGNAL ;
    PORT
      LAYER M4 ;
        RECT  0 22.224 0.084 22.248 ;
    END
  END b[93]
  PIN b[94]
    DIRECTION OUTPUT ;
    USE SIGNAL ;
    PORT
      LAYER M4 ;
        RECT  0 22.32 0.084 22.344 ;
    END
  END b[94]
  PIN b[95]
    DIRECTION OUTPUT ;
    USE SIGNAL ;
    PORT
      LAYER M4 ;
        RECT  0 22.416 0.084 22.44 ;
    END
  END b[95]
  PIN b[96]
    DIRECTION OUTPUT ;
    USE SIGNAL ;
    PORT
      LAYER M4 ;
        RECT  0 13.296 0.084 13.32 ;
    END
  END b[96]
  PIN b[97]
    DIRECTION OUTPUT ;
    USE SIGNAL ;
    PORT
      LAYER M4 ;
        RECT  0 13.392 0.084 13.416 ;
    END
  END b[97]
  PIN b[98]
    DIRECTION OUTPUT ;
    USE SIGNAL ;
    PORT
      LAYER M4 ;
        RECT  0 13.488 0.084 13.512 ;
    END
  END b[98]
  PIN b[99]
    DIRECTION OUTPUT ;
    USE SIGNAL ;
    PORT
      LAYER M4 ;
        RECT  0 13.584 0.084 13.608 ;
    END
  END b[99]
  PIN b[9]
    DIRECTION OUTPUT ;
    USE SIGNAL ;
    PORT
      LAYER M4 ;
        RECT  0 23.376 0.084 23.4 ;
    END
  END b[9]
  PIN ck_o
    DIRECTION OUTPUT ;
    USE SIGNAL ;
    PORT
      LAYER M4 ;
        RECT  0 28.464 0.084 28.488 ;
    END
  END ck_o
  PIN ckf
    DIRECTION INPUT ;
    USE SIGNAL ;
    PORT
      LAYER M4 ;
        RECT  21.516 4.56 21.6 4.584 ;
    END
  END ckf
  PIN ea
    DIRECTION INPUT ;
    USE SIGNAL ;
    PORT
      LAYER M4 ;
        RECT  21.516 4.656 21.6 4.68 ;
    END
  END ea
  PIN eb
    DIRECTION OUTPUT ;
    USE SIGNAL ;
    PORT
      LAYER M4 ;
        RECT  0 28.56 0.084 28.584 ;
    END
  END eb
  PIN VDD
    DIRECTION INOUT ;
    USE POWER ;
    PORT
      LAYER M5 ;
        RECT  18.792 2.151 18.912 30.249 ;
        RECT  16.092 2.151 16.212 30.249 ;
        RECT  13.392 2.151 13.512 30.249 ;
        RECT  10.692 2.151 10.812 30.249 ;
        RECT  7.992 2.151 8.112 30.249 ;
        RECT  5.292 2.151 5.412 30.249 ;
        RECT  2.592 2.151 2.712 30.249 ;
    END
  END VDD
  PIN VSS
    DIRECTION INOUT ;
    USE GROUND ;
    PORT
      LAYER M5 ;
        RECT  18.6 2.137 18.72 30.263 ;
        RECT  15.9 2.137 16.02 30.263 ;
        RECT  13.2 2.137 13.32 30.263 ;
        RECT  10.5 2.137 10.62 30.263 ;
        RECT  7.8 2.137 7.92 30.263 ;
        RECT  5.1 2.137 5.22 30.263 ;
        RECT  2.4 2.137 2.52 30.263 ;
    END
  END VSS
  # OT_OBS_CLOSED layer=M5 d_um=1.536 added=13
  OBS
    LAYER RVTN ;
     RECT  2.16 2.16 19.44 2.295 ;
     RECT  2.16 2.565 19.44 2.835 ;
     RECT  2.16 3.105 19.44 3.375 ;
     RECT  2.16 3.645 19.44 3.915 ;
     RECT  2.16 4.185 19.44 4.455 ;
     RECT  2.16 4.725 19.44 4.995 ;
     RECT  2.16 5.265 19.44 5.535 ;
     RECT  2.16 5.805 19.44 6.075 ;
     RECT  2.16 6.345 19.44 6.615 ;
     RECT  2.16 6.885 19.44 7.155 ;
     RECT  2.16 7.425 19.44 7.695 ;
     RECT  2.16 7.965 19.44 8.235 ;
     RECT  2.16 8.505 19.44 8.775 ;
     RECT  2.16 9.045 19.44 9.315 ;
     RECT  2.16 9.585 19.44 9.855 ;
     RECT  2.16 10.125 19.44 10.395 ;
     RECT  2.16 10.665 19.44 10.935 ;
     RECT  2.16 11.205 19.44 11.475 ;
     RECT  2.16 11.745 19.44 12.015 ;
     RECT  2.16 12.285 19.44 12.555 ;
     RECT  2.16 12.825 19.44 13.095 ;
     RECT  2.16 13.365 19.44 13.635 ;
     RECT  2.16 13.905 19.44 14.175 ;
     RECT  2.16 14.445 19.44 14.715 ;
     RECT  2.16 14.985 19.44 15.255 ;
     RECT  2.16 15.525 19.44 15.795 ;
     RECT  2.16 16.065 19.44 16.335 ;
     RECT  2.16 16.605 19.44 16.875 ;
     RECT  2.16 17.145 19.44 17.415 ;
     RECT  2.16 17.685 19.44 17.955 ;
     RECT  2.16 18.225 19.44 18.495 ;
     RECT  2.16 18.765 19.44 19.035 ;
     RECT  2.16 19.305 19.44 19.575 ;
     RECT  2.16 19.845 19.44 20.115 ;
     RECT  2.16 20.385 19.44 20.655 ;
     RECT  2.16 20.925 19.44 21.195 ;
     RECT  2.16 21.465 19.44 21.735 ;
     RECT  2.16 22.005 19.44 22.275 ;
     RECT  2.16 22.545 19.44 22.815 ;
     RECT  2.16 23.085 19.44 23.355 ;
     RECT  2.16 23.625 19.44 23.895 ;
     RECT  2.16 24.165 19.44 24.435 ;
     RECT  2.16 24.705 19.44 24.975 ;
     RECT  2.16 25.245 19.44 25.515 ;
     RECT  2.16 25.785 19.44 26.055 ;
     RECT  2.16 26.325 19.44 26.595 ;
     RECT  2.16 26.865 19.44 27.135 ;
     RECT  2.16 27.405 19.44 27.675 ;
     RECT  2.16 27.945 19.44 28.215 ;
     RECT  2.16 28.485 19.44 28.755 ;
     RECT  2.16 29.025 19.44 29.295 ;
     RECT  2.16 29.565 19.44 29.835 ;
     RECT  2.16 30.105 19.44 30.24 ;
    LAYER RVTP ;
     RECT  2.16 2.295 19.44 2.565 ;
     RECT  2.16 2.835 19.44 3.105 ;
     RECT  2.16 3.375 19.44 3.645 ;
     RECT  2.16 3.915 19.44 4.185 ;
     RECT  2.16 4.455 19.44 4.725 ;
     RECT  2.16 4.995 19.44 5.265 ;
     RECT  2.16 5.535 19.44 5.805 ;
     RECT  2.16 6.075 19.44 6.345 ;
     RECT  2.16 6.615 19.44 6.885 ;
     RECT  2.16 7.155 19.44 7.425 ;
     RECT  2.16 7.695 19.44 7.965 ;
     RECT  2.16 8.235 19.44 8.505 ;
     RECT  2.16 8.775 19.44 9.045 ;
     RECT  2.16 9.315 19.44 9.585 ;
     RECT  2.16 9.855 19.44 10.125 ;
     RECT  2.16 10.395 19.44 10.665 ;
     RECT  2.16 10.935 19.44 11.205 ;
     RECT  2.16 11.475 19.44 11.745 ;
     RECT  2.16 12.015 19.44 12.285 ;
     RECT  2.16 12.555 19.44 12.825 ;
     RECT  2.16 13.095 19.44 13.365 ;
     RECT  2.16 13.635 19.44 13.905 ;
     RECT  2.16 14.175 19.44 14.445 ;
     RECT  2.16 14.715 19.44 14.985 ;
     RECT  2.16 15.255 19.44 15.525 ;
     RECT  2.16 15.795 19.44 16.065 ;
     RECT  2.16 16.335 19.44 16.605 ;
     RECT  2.16 16.875 19.44 17.145 ;
     RECT  2.16 17.415 19.44 17.685 ;
     RECT  2.16 17.955 19.44 18.225 ;
     RECT  2.16 18.495 19.44 18.765 ;
     RECT  2.16 19.035 19.44 19.305 ;
     RECT  2.16 19.575 19.44 19.845 ;
     RECT  2.16 20.115 19.44 20.385 ;
     RECT  2.16 20.655 19.44 20.925 ;
     RECT  2.16 21.195 19.44 21.465 ;
     RECT  2.16 21.735 19.44 22.005 ;
     RECT  2.16 22.275 19.44 22.545 ;
     RECT  2.16 22.815 19.44 23.085 ;
     RECT  2.16 23.355 19.44 23.625 ;
     RECT  2.16 23.895 19.44 24.165 ;
     RECT  2.16 24.435 19.44 24.705 ;
     RECT  2.16 24.975 19.44 25.245 ;
     RECT  2.16 25.515 19.44 25.785 ;
     RECT  2.16 26.055 19.44 26.325 ;
     RECT  2.16 26.595 19.44 26.865 ;
     RECT  2.16 27.135 19.44 27.405 ;
     RECT  2.16 27.675 19.44 27.945 ;
     RECT  2.16 28.215 19.44 28.485 ;
     RECT  2.16 28.755 19.44 29.025 ;
     RECT  2.16 29.295 19.44 29.565 ;
     RECT  2.16 29.835 19.44 30.105 ;
    LAYER M1 ;
     RECT  2.16 2.151 19.44 30.249 ;
    LAYER M2 ;
     RECT  0.103 16.146 0.203 16.164 ;
     RECT  0.103 17.082 0.203 17.1 ;
     RECT  0.103 18.621 0.203 18.639 ;
     RECT  0.103 20.241 0.203 20.259 ;
     RECT  0.211 22.788 0.247 22.806 ;
     RECT  0.103 21.132 0.283 21.15 ;
     RECT  0.247 22.518 0.283 22.806 ;
     RECT  0.283 21.132 0.319 21.384 ;
     RECT  0.283 22.518 0.319 23.229 ;
     RECT  0.139 14.652 0.383 14.67 ;
     RECT  0.319 21.132 0.391 23.544 ;
     RECT  0.391 21.132 0.427 24.264 ;
     RECT  0.427 21.132 0.499 24.498 ;
     RECT  0.031 27.801 0.499 27.819 ;
     RECT  0.499 12.906 0.535 12.924 ;
     RECT  0.463 20.358 0.535 20.376 ;
     RECT  0.499 21.132 0.535 24.966 ;
     RECT  0.499 27.684 0.535 27.819 ;
     RECT  0.031 5.436 2.16 5.454 ;
     RECT  0.067 9.828 2.16 9.846 ;
     RECT  0.103 10.71 2.16 10.728 ;
     RECT  0.823 11.826 2.16 11.844 ;
     RECT  0.535 12.906 2.16 13.014 ;
     RECT  0.535 14.724 2.16 14.742 ;
     RECT  0.535 16.506 2.16 16.524 ;
     RECT  0.535 20.358 2.16 24.966 ;
     RECT  0.103 26.766 2.16 26.784 ;
     RECT  0.535 27.684 2.16 27.864 ;
     RECT  2.16 2.151 19.44 30.249 ;
     RECT  19.44 6.696 19.967 19.098 ;
     RECT  19.967 9.396 20.435 19.098 ;
     RECT  19.44 3.888 20.507 4.95 ;
     RECT  19.967 6.696 20.507 8.604 ;
     RECT  20.435 9.396 20.507 11.844 ;
     RECT  20.435 12.906 20.507 19.098 ;
     RECT  20.507 18.702 20.543 18.72 ;
     RECT  20.507 6.696 20.579 7.254 ;
     RECT  20.507 17.73 20.579 17.748 ;
     RECT  20.579 7.236 21.415 7.254 ;
     RECT  20.507 15.768 21.443 16.596 ;
     RECT  20.507 4.194 21.479 4.95 ;
     RECT  20.507 10.476 21.479 11.844 ;
     RECT  21.479 4.194 21.515 4.788 ;
     RECT  21.415 7.236 21.515 7.524 ;
     RECT  20.507 8.586 21.515 8.604 ;
     RECT  20.507 9.594 21.515 9.612 ;
     RECT  21.479 10.476 21.515 10.494 ;
     RECT  21.479 11.754 21.515 11.772 ;
     RECT  20.507 13.41 21.515 13.428 ;
     RECT  20.507 14.256 21.515 14.508 ;
     RECT  21.443 16.11 21.515 16.398 ;
     RECT  21.415 17.496 21.515 17.514 ;
    LAYER M3 ;
     RECT  2.415 2.143 2.505 2.413 ;
     RECT  5.115 2.143 5.205 2.413 ;
     RECT  7.815 2.143 7.905 2.413 ;
     RECT  10.515 2.143 10.605 2.413 ;
     RECT  13.215 2.143 13.305 2.413 ;
     RECT  15.915 2.143 16.005 2.413 ;
     RECT  18.615 2.143 18.705 2.413 ;
     RECT  18.615 2.413 18.897 3.811 ;
     RECT  19.908 3.787 19.926 3.883 ;
     RECT  19.908 3.883 20.502 3.947 ;
     RECT  18.144 3.811 18.897 3.979 ;
     RECT  18.144 3.979 18.99 4.153 ;
     RECT  10.515 2.413 10.797 4.189 ;
     RECT  13.215 2.413 13.497 4.189 ;
     RECT  18.144 4.153 19.422 4.205 ;
     RECT  15.915 2.413 16.197 4.225 ;
     RECT  17.208 3.955 17.226 4.225 ;
     RECT  18.144 4.205 19.386 4.225 ;
     RECT  10.515 4.189 10.854 4.261 ;
     RECT  13.104 4.189 13.497 4.261 ;
     RECT  14.4 3.991 14.418 4.261 ;
     RECT  20.484 3.947 20.502 4.415 ;
     RECT  15.732 4.225 16.197 4.495 ;
     RECT  15.624 4.495 16.197 4.507 ;
     RECT  17.208 4.225 19.386 4.507 ;
     RECT  12.924 4.261 13.497 4.523 ;
     RECT  15.624 4.507 19.386 4.523 ;
     RECT  2.415 2.413 2.697 4.531 ;
     RECT  12.132 4.495 12.15 4.541 ;
     RECT  13.215 4.523 13.497 4.555 ;
     RECT  14.4 4.261 14.85 4.555 ;
     RECT  15.624 4.523 19.17 4.555 ;
     RECT  21.492 4.075 21.51 4.555 ;
     RECT  2.415 4.531 3.114 4.621 ;
     RECT  4.032 4.423 4.05 4.621 ;
     RECT  10.26 4.261 10.854 4.685 ;
     RECT  21.312 4.555 21.51 4.685 ;
     RECT  10.515 4.685 10.854 4.729 ;
     RECT  13.215 4.555 13.59 4.765 ;
     RECT  14.4 4.555 19.17 4.765 ;
     RECT  21.456 4.685 21.51 4.793 ;
     RECT  6.804 4.729 6.822 4.829 ;
     RECT  10.515 4.729 10.926 4.919 ;
     RECT  21.456 4.793 21.474 4.955 ;
     RECT  13.215 4.765 19.17 5.027 ;
     RECT  2.415 4.621 4.05 5.071 ;
     RECT  13.215 5.027 16.197 5.099 ;
     RECT  18.144 5.027 18.897 5.099 ;
     RECT  13.215 5.099 14.85 5.495 ;
     RECT  14.508 5.495 14.85 5.999 ;
     RECT  7.815 2.413 8.097 6.151 ;
     RECT  15.915 5.099 16.197 6.655 ;
     RECT  16.992 6.619 17.01 6.655 ;
     RECT  15.915 6.655 17.01 6.781 ;
     RECT  15.876 6.781 17.01 6.811 ;
     RECT  20.556 6.691 20.574 6.817 ;
     RECT  15.876 6.811 17.478 6.853 ;
     RECT  18.615 5.099 18.897 6.889 ;
     RECT  14.508 5.999 14.562 6.925 ;
     RECT  15.876 6.853 17.694 6.925 ;
     RECT  18.615 6.889 19.422 6.925 ;
     RECT  20.52 6.817 20.574 6.989 ;
     RECT  13.215 5.495 13.497 7.051 ;
     RECT  14.508 6.925 14.922 7.051 ;
     RECT  15.876 6.925 19.422 7.051 ;
     RECT  15.876 7.051 20.43 7.159 ;
     RECT  13.215 7.051 14.994 7.231 ;
     RECT  21.492 7.147 21.51 7.483 ;
     RECT  10.515 4.919 10.797 7.501 ;
     RECT  11.7 7.159 11.718 7.501 ;
     RECT  21.42 7.483 21.51 7.529 ;
     RECT  21.492 7.529 21.51 7.565 ;
     RECT  13.032 7.231 14.994 7.627 ;
     RECT  12.708 7.627 14.994 7.663 ;
     RECT  15.768 7.159 20.43 7.663 ;
     RECT  12.708 7.663 20.43 7.723 ;
     RECT  12.708 7.723 20.502 7.925 ;
     RECT  21.492 8.491 21.51 8.609 ;
     RECT  13.104 7.925 20.502 9.355 ;
     RECT  21.492 9.451 21.51 9.617 ;
     RECT  12.888 9.355 20.502 9.625 ;
     RECT  0.036 5.431 0.054 9.823 ;
     RECT  12.528 9.625 20.502 9.959 ;
     RECT  19.908 9.959 20.502 9.965 ;
     RECT  10.515 7.501 11.718 10.201 ;
     RECT  12.528 9.959 18.918 10.201 ;
     RECT  0.036 9.823 0.09 10.705 ;
     RECT  2.415 5.071 4.23 10.831 ;
     RECT  10.515 10.201 18.918 10.891 ;
     RECT  19.908 9.965 20.322 10.891 ;
     RECT  6.912 10.867 6.93 10.903 ;
     RECT  2.415 10.831 4.338 10.931 ;
     RECT  21.492 10.411 21.51 10.987 ;
     RECT  6.804 10.903 6.93 11.039 ;
     RECT  10.515 10.891 20.322 11.173 ;
     RECT  21.456 10.987 21.51 11.227 ;
     RECT  5.115 2.413 5.397 11.281 ;
     RECT  10.515 11.173 20.502 11.405 ;
     RECT  21.42 11.227 21.51 11.405 ;
     RECT  12.78 11.405 20.502 11.443 ;
     RECT  12.78 11.443 20.574 11.597 ;
     RECT  21.456 11.405 21.51 11.777 ;
     RECT  0.036 10.705 0.126 11.821 ;
     RECT  21.456 11.777 21.474 11.849 ;
     RECT  6.804 11.039 6.822 12.019 ;
     RECT  4.968 11.281 5.397 12.055 ;
     RECT  6.228 12.019 6.822 12.055 ;
     RECT  4.968 12.055 6.822 12.091 ;
     RECT  4.968 12.091 6.858 12.209 ;
     RECT  12.78 11.597 20.43 12.217 ;
     RECT  6.336 12.209 6.858 12.281 ;
     RECT  21.42 12.139 21.438 12.317 ;
     RECT  7.815 6.151 8.766 12.361 ;
     RECT  12.708 12.217 20.43 12.715 ;
     RECT  7.596 12.361 8.766 12.721 ;
     RECT  10.515 11.405 11.97 12.721 ;
     RECT  12.708 12.715 20.502 12.721 ;
     RECT  10.515 12.721 20.502 12.857 ;
     RECT  6.336 12.281 6.354 13.339 ;
     RECT  7.272 12.721 8.766 13.339 ;
     RECT  2.415 10.931 4.23 13.432 ;
     RECT  4.968 12.209 5.562 13.432 ;
     RECT  2.415 13.432 5.562 13.441 ;
     RECT  19.872 12.857 20.502 13.739 ;
     RECT  6.336 13.339 8.766 13.828 ;
     RECT  10.515 12.857 18.954 13.963 ;
     RECT  19.872 13.739 20.43 13.963 ;
     RECT  2.304 13.441 5.562 14.009 ;
     RECT  10.515 13.963 20.43 14.243 ;
     RECT  10.515 14.243 18.99 14.251 ;
     RECT  10.404 14.251 18.99 14.405 ;
     RECT  21.492 13.291 21.51 14.513 ;
     RECT  6.336 13.828 9.198 14.521 ;
     RECT  6.336 14.521 9.702 14.549 ;
     RECT  19.836 14.243 20.43 14.635 ;
     RECT  6.336 14.549 8.766 14.675 ;
     RECT  0.036 11.821 0.846 14.861 ;
     RECT  2.415 14.009 5.562 15.061 ;
     RECT  2.34 15.061 5.562 15.115 ;
     RECT  2.304 15.115 5.562 15.179 ;
     RECT  9.684 14.549 9.702 15.187 ;
     RECT  10.515 14.405 18.99 15.187 ;
     RECT  9.684 15.187 18.99 15.295 ;
     RECT  19.836 14.635 20.502 15.295 ;
     RECT  9.684 15.295 20.502 15.593 ;
     RECT  2.304 15.179 5.397 15.725 ;
     RECT  9.792 15.593 20.502 15.827 ;
     RECT  0.036 14.861 0.054 15.835 ;
     RECT  0.828 14.861 0.846 15.835 ;
     RECT  21.42 15.691 21.438 15.979 ;
     RECT  2.415 15.725 5.397 16.025 ;
     RECT  20.448 15.827 20.502 16.303 ;
     RECT  20.448 16.303 20.538 16.397 ;
     RECT  21.42 15.979 21.51 16.403 ;
     RECT  3.924 16.025 5.397 16.411 ;
     RECT  3.924 16.411 5.454 16.529 ;
     RECT  21.42 16.403 21.438 16.601 ;
     RECT  20.448 16.397 20.502 16.651 ;
     RECT  6.48 14.675 8.766 16.673 ;
     RECT  9.792 15.827 19.422 16.781 ;
     RECT  3.924 16.529 5.397 16.835 ;
     RECT  20.412 16.651 20.502 16.843 ;
     RECT  2.415 16.025 3.114 16.951 ;
     RECT  20.376 16.843 20.502 16.951 ;
     RECT  9.792 16.781 19.062 17.105 ;
     RECT  9.828 17.105 19.062 17.117 ;
     RECT  2.376 16.951 3.114 17.311 ;
     RECT  3.924 16.835 4.302 17.447 ;
     RECT  21.42 17.467 21.438 17.491 ;
     RECT  21.42 17.491 21.51 17.519 ;
     RECT  21.492 17.519 21.51 17.549 ;
     RECT  9.828 17.117 19.026 17.609 ;
     RECT  6.876 16.673 8.766 17.659 ;
     RECT  19.872 16.951 20.502 17.725 ;
     RECT  5.115 16.835 5.397 17.752 ;
     RECT  19.872 17.725 20.574 17.933 ;
     RECT  10.515 17.609 19.026 17.995 ;
     RECT  19.872 17.933 20.502 17.995 ;
     RECT  10.515 17.995 20.502 18.023 ;
     RECT  5.004 17.752 5.397 18.329 ;
     RECT  2.304 17.311 3.114 18.419 ;
     RECT  10.515 18.023 19.386 18.455 ;
     RECT  6.84 17.659 8.766 18.509 ;
     RECT  13.032 18.455 19.386 18.599 ;
     RECT  20.412 18.023 20.502 18.697 ;
     RECT  20.412 18.697 20.538 18.763 ;
     RECT  7.776 18.509 8.766 18.845 ;
     RECT  19.872 18.763 20.538 18.893 ;
     RECT  19.872 18.893 20.502 19.031 ;
     RECT  10.515 18.455 11.97 19.037 ;
     RECT  5.115 18.329 5.397 19.099 ;
     RECT  20.484 19.031 20.502 19.103 ;
     RECT  5.115 19.099 5.49 19.139 ;
     RECT  13.032 18.599 18.99 19.139 ;
     RECT  13.032 19.139 18.897 19.201 ;
     RECT  2.415 18.419 3.114 19.435 ;
     RECT  5.115 19.139 5.397 19.471 ;
     RECT  6.84 18.509 6.894 19.483 ;
     RECT  12.744 19.201 18.897 19.805 ;
     RECT  10.515 19.037 11.61 19.912 ;
     RECT  10.404 19.912 11.61 19.949 ;
     RECT  10.515 19.949 11.61 19.963 ;
     RECT  6.84 19.483 6.966 20.011 ;
     RECT  6.84 20.011 7.074 20.141 ;
     RECT  6.84 20.141 7.002 20.333 ;
     RECT  12.816 19.805 18.897 20.345 ;
     RECT  6.984 20.333 7.002 20.477 ;
     RECT  5.004 19.471 5.397 20.489 ;
     RECT  2.304 19.435 3.114 20.525 ;
     RECT  7.815 18.845 8.766 20.683 ;
     RECT  5.115 20.489 5.397 20.821 ;
     RECT  7.815 20.683 9.162 20.861 ;
     RECT  10.515 19.963 11.97 20.909 ;
     RECT  5.115 20.821 5.49 21.199 ;
     RECT  12.96 20.345 18.897 21.199 ;
     RECT  5.115 21.199 5.562 21.299 ;
     RECT  12.708 21.199 18.897 21.299 ;
     RECT  2.415 20.525 3.114 21.631 ;
     RECT  5.115 21.299 5.397 21.631 ;
     RECT  2.304 21.631 3.114 21.677 ;
     RECT  5.004 21.631 5.397 21.677 ;
     RECT  6.84 21.163 6.858 21.773 ;
     RECT  10.515 20.909 11.61 21.965 ;
     RECT  13.104 21.299 18.897 22.775 ;
     RECT  13.104 22.775 17.586 22.891 ;
     RECT  2.415 21.677 3.114 22.981 ;
     RECT  10.515 21.965 11.394 23.117 ;
     RECT  2.304 22.981 3.114 23.213 ;
     RECT  10.515 23.117 10.926 23.279 ;
     RECT  13.068 22.891 17.586 23.315 ;
     RECT  17.496 23.315 17.586 23.351 ;
     RECT  18.432 22.775 18.897 23.351 ;
     RECT  17.568 23.351 17.586 23.549 ;
     RECT  13.068 23.315 16.614 23.693 ;
     RECT  13.068 23.693 16.578 23.899 ;
     RECT  10.515 23.279 10.797 24.169 ;
     RECT  10.515 24.169 10.854 24.241 ;
     RECT  2.415 23.213 3.114 24.331 ;
     RECT  5.115 21.677 5.397 24.331 ;
     RECT  17.676 23.701 17.694 24.331 ;
     RECT  12.492 23.899 16.578 24.365 ;
     RECT  2.304 24.331 3.114 24.368 ;
     RECT  5.004 24.331 5.397 24.368 ;
     RECT  17.64 24.331 17.694 24.395 ;
     RECT  10.515 24.241 10.926 24.431 ;
     RECT  18.576 23.351 18.897 24.431 ;
     RECT  6.84 24.331 6.858 24.461 ;
     RECT  9.648 24.439 9.666 24.653 ;
     RECT  17.64 24.395 17.658 24.773 ;
     RECT  12.996 24.365 16.578 24.781 ;
     RECT  12.996 24.781 16.686 24.899 ;
     RECT  12.996 24.899 13.497 24.935 ;
     RECT  14.22 24.899 16.686 24.935 ;
     RECT  15.48 24.935 16.686 24.941 ;
     RECT  14.22 24.935 14.526 24.971 ;
     RECT  10.515 24.431 10.854 24.979 ;
     RECT  10.26 24.979 10.854 25.043 ;
     RECT  13.104 24.935 13.497 25.079 ;
     RECT  15.48 24.941 16.197 25.079 ;
     RECT  5.115 24.368 5.397 25.141 ;
     RECT  5.115 25.141 5.49 25.181 ;
     RECT  10.26 25.043 10.797 25.277 ;
     RECT  0.036 15.835 0.846 25.421 ;
     RECT  0.036 25.421 0.054 26.761 ;
     RECT  0.828 25.421 0.846 26.761 ;
     RECT  3.924 17.447 4.23 26.789 ;
     RECT  7.815 20.861 8.766 27.509 ;
     RECT  3.96 26.789 4.23 27.635 ;
     RECT  0.036 26.761 0.846 27.824 ;
     RECT  2.415 24.368 3.114 27.905 ;
     RECT  2.415 27.905 2.862 27.917 ;
     RECT  0.108 27.824 0.846 28.013 ;
     RECT  0.108 28.013 0.558 28.109 ;
     RECT  14.508 24.971 14.526 28.175 ;
     RECT  0.108 28.109 0.522 28.205 ;
     RECT  13.215 25.079 13.497 28.267 ;
     RECT  2.415 27.917 2.697 28.291 ;
     RECT  12.564 28.267 13.497 28.319 ;
     RECT  0.108 28.205 0.126 28.397 ;
     RECT  4.212 27.635 4.23 28.489 ;
     RECT  2.412 28.291 2.697 28.555 ;
     RECT  2.304 28.555 2.697 28.787 ;
     RECT  4.14 28.489 4.23 28.831 ;
     RECT  5.115 25.181 5.397 28.831 ;
     RECT  2.415 28.787 2.697 28.891 ;
     RECT  3.42 28.831 5.397 28.891 ;
     RECT  2.415 28.891 5.397 28.949 ;
     RECT  4.104 28.949 4.158 28.985 ;
     RECT  4.14 28.985 4.158 29.021 ;
     RECT  2.415 28.949 2.697 29.987 ;
     RECT  5.115 28.949 5.397 29.987 ;
     RECT  7.815 27.509 8.097 29.987 ;
     RECT  10.515 25.277 10.797 29.987 ;
     RECT  13.215 28.319 13.497 29.987 ;
     RECT  15.915 25.079 16.197 29.987 ;
     RECT  18.615 24.431 18.897 29.987 ;
     RECT  2.415 29.987 2.505 30.257 ;
     RECT  5.115 29.987 5.205 30.257 ;
     RECT  7.815 29.987 7.905 30.257 ;
     RECT  10.515 29.987 10.605 30.257 ;
     RECT  13.215 29.987 13.305 30.257 ;
     RECT  15.915 29.987 16.005 30.257 ;
     RECT  18.615 29.987 18.705 30.257 ;
    LAYER M4 ;
     RECT  0.06 13.32 0.061 13.392 ;
     RECT  0.06 13.416 0.061 13.488 ;
     RECT  0.06 13.512 0.061 13.584 ;
     RECT  0.06 13.608 0.061 13.68 ;
     RECT  0.06 13.704 0.061 13.776 ;
     RECT  0.06 13.8 0.061 13.872 ;
     RECT  0.06 13.896 0.061 13.968 ;
     RECT  0.06 13.992 0.061 14.064 ;
     RECT  0.06 14.088 0.061 14.16 ;
     RECT  0.06 14.184 0.061 14.256 ;
     RECT  0.06 14.28 0.061 14.352 ;
     RECT  0.06 14.376 0.061 14.448 ;
     RECT  0.06 14.472 0.061 14.544 ;
     RECT  0.06 14.568 0.061 14.64 ;
     RECT  0.06 14.664 0.061 14.736 ;
     RECT  0.06 14.76 0.061 14.832 ;
     RECT  0.06 14.856 0.061 14.928 ;
     RECT  0.06 14.952 0.061 15.024 ;
     RECT  0.06 15.048 0.061 15.12 ;
     RECT  0.06 15.144 0.061 15.216 ;
     RECT  0.06 15.24 0.061 15.312 ;
     RECT  0.06 15.336 0.061 15.408 ;
     RECT  0.06 15.432 0.061 15.504 ;
     RECT  0.06 15.528 0.061 15.6 ;
     RECT  0.06 15.624 0.061 15.696 ;
     RECT  0.06 15.72 0.061 15.792 ;
     RECT  0.06 15.816 0.061 15.888 ;
     RECT  0.06 15.912 0.061 15.984 ;
     RECT  0.06 16.008 0.061 16.08 ;
     RECT  0.06 16.104 0.061 16.176 ;
     RECT  0.06 16.2 0.061 16.272 ;
     RECT  0.06 16.296 0.061 16.368 ;
     RECT  0.06 16.392 0.061 16.464 ;
     RECT  0.06 16.488 0.061 16.56 ;
     RECT  0.06 16.584 0.061 16.656 ;
     RECT  0.06 16.68 0.061 16.752 ;
     RECT  0.06 16.776 0.061 16.848 ;
     RECT  0.06 16.872 0.061 16.944 ;
     RECT  0.06 16.968 0.061 17.04 ;
     RECT  0.06 17.064 0.061 17.136 ;
     RECT  0.06 17.16 0.061 17.232 ;
     RECT  0.06 17.256 0.061 17.328 ;
     RECT  0.06 17.352 0.061 17.424 ;
     RECT  0.06 17.448 0.061 17.52 ;
     RECT  0.06 17.544 0.061 17.616 ;
     RECT  0.06 17.64 0.061 17.712 ;
     RECT  0.06 17.736 0.061 17.808 ;
     RECT  0.06 17.832 0.061 17.904 ;
     RECT  0.06 17.928 0.061 18 ;
     RECT  0.06 18.024 0.061 18.096 ;
     RECT  0.06 18.12 0.061 18.192 ;
     RECT  0.06 18.216 0.061 18.288 ;
     RECT  0.06 18.312 0.061 18.384 ;
     RECT  0.06 18.408 0.061 18.48 ;
     RECT  0.06 18.504 0.061 18.576 ;
     RECT  0.06 18.6 0.061 18.672 ;
     RECT  0.06 18.696 0.061 18.768 ;
     RECT  0.06 18.792 0.061 18.864 ;
     RECT  0.06 18.888 0.061 18.96 ;
     RECT  0.06 18.984 0.061 19.056 ;
     RECT  0.06 19.08 0.061 19.152 ;
     RECT  0.06 19.176 0.061 19.248 ;
     RECT  0.06 19.272 0.061 19.344 ;
     RECT  0.06 19.368 0.061 19.44 ;
     RECT  0.06 19.464 0.061 19.536 ;
     RECT  0.06 19.56 0.061 19.632 ;
     RECT  0.06 19.656 0.061 19.728 ;
     RECT  0.06 19.752 0.061 19.824 ;
     RECT  0.06 19.848 0.061 19.92 ;
     RECT  0.06 19.944 0.061 20.016 ;
     RECT  0.06 20.04 0.061 20.112 ;
     RECT  0.06 20.136 0.061 20.208 ;
     RECT  0.06 20.232 0.061 20.304 ;
     RECT  0.06 20.328 0.061 20.4 ;
     RECT  0.06 20.424 0.061 20.496 ;
     RECT  0.06 20.52 0.061 20.592 ;
     RECT  0.06 20.616 0.061 20.688 ;
     RECT  0.06 20.712 0.061 20.784 ;
     RECT  0.06 20.808 0.061 20.88 ;
     RECT  0.06 20.904 0.061 20.976 ;
     RECT  0.06 21 0.061 21.072 ;
     RECT  0.06 21.096 0.061 21.168 ;
     RECT  0.06 21.192 0.061 21.264 ;
     RECT  0.06 21.288 0.061 21.36 ;
     RECT  0.06 21.384 0.061 21.456 ;
     RECT  0.06 21.48 0.061 21.552 ;
     RECT  0.06 21.576 0.061 21.648 ;
     RECT  0.06 21.672 0.061 21.744 ;
     RECT  0.06 21.768 0.061 21.84 ;
     RECT  0.06 21.864 0.061 21.936 ;
     RECT  0.06 21.96 0.061 22.032 ;
     RECT  0.06 22.056 0.061 22.128 ;
     RECT  0.06 22.152 0.061 22.224 ;
     RECT  0.06 22.248 0.061 22.32 ;
     RECT  0.06 22.344 0.061 22.416 ;
     RECT  0.06 22.44 0.061 22.512 ;
     RECT  0.06 22.536 0.061 22.608 ;
     RECT  0.06 22.632 0.061 22.704 ;
     RECT  0.06 22.728 0.061 22.8 ;
     RECT  0.06 22.824 0.061 22.896 ;
     RECT  0.06 22.92 0.061 22.992 ;
     RECT  0.06 23.016 0.061 23.088 ;
     RECT  0.06 23.112 0.061 23.184 ;
     RECT  0.06 23.208 0.061 23.28 ;
     RECT  0.06 23.304 0.061 23.376 ;
     RECT  0.06 23.4 0.061 23.472 ;
     RECT  0.06 23.496 0.061 23.568 ;
     RECT  0.06 23.592 0.061 23.664 ;
     RECT  0.06 23.688 0.061 23.76 ;
     RECT  0.06 23.784 0.061 23.856 ;
     RECT  0.06 23.88 0.061 23.952 ;
     RECT  0.06 23.976 0.061 24.048 ;
     RECT  0.06 24.072 0.061 24.144 ;
     RECT  0.06 24.168 0.061 24.24 ;
     RECT  0.06 24.264 0.061 24.336 ;
     RECT  0.06 24.36 0.061 24.432 ;
     RECT  0.06 24.456 0.061 24.528 ;
     RECT  0.06 24.552 0.061 24.624 ;
     RECT  0.06 24.648 0.061 24.72 ;
     RECT  0.06 24.744 0.061 24.816 ;
     RECT  0.06 24.84 0.061 24.912 ;
     RECT  0.06 24.936 0.061 25.008 ;
     RECT  0.06 25.032 0.061 25.104 ;
     RECT  0.06 25.128 0.061 25.2 ;
     RECT  0.06 25.224 0.061 25.296 ;
     RECT  0.06 25.32 0.061 25.392 ;
     RECT  0.06 25.416 0.061 25.488 ;
     RECT  0.084 27.696 0.137 27.72 ;
     RECT  0.06 27.72 0.137 27.792 ;
     RECT  0.084 27.792 0.137 27.816 ;
     RECT  0.06 27.816 0.137 27.888 ;
     RECT  0.084 27.888 0.137 27.912 ;
     RECT  0.06 27.912 0.137 27.984 ;
     RECT  0.084 27.984 0.137 28.008 ;
     RECT  0.06 28.008 0.137 28.08 ;
     RECT  0.084 28.08 0.137 28.104 ;
     RECT  0.06 28.104 0.137 28.176 ;
     RECT  0.084 28.176 0.137 28.2 ;
     RECT  0.06 28.2 0.137 28.272 ;
     RECT  0.084 28.272 0.137 28.296 ;
     RECT  0.06 28.296 0.137 28.368 ;
     RECT  0.084 28.368 0.137 28.392 ;
     RECT  0.06 28.392 0.137 28.464 ;
     RECT  0.084 28.464 0.137 28.488 ;
     RECT  0.06 28.488 0.137 28.56 ;
     RECT  0.084 28.56 0.137 28.584 ;
     RECT  0.061 13.2 0.173 13.296 ;
     RECT  0.084 13.296 0.173 13.32 ;
     RECT  0.061 13.32 0.173 13.392 ;
     RECT  0.084 13.392 0.173 13.416 ;
     RECT  0.061 13.416 0.173 13.488 ;
     RECT  0.084 13.488 0.173 13.512 ;
     RECT  0.061 13.512 0.173 13.584 ;
     RECT  0.084 13.584 0.173 13.608 ;
     RECT  0.061 13.608 0.173 13.68 ;
     RECT  0.084 13.68 0.173 13.704 ;
     RECT  0.061 13.704 0.173 13.776 ;
     RECT  0.084 13.776 0.173 13.8 ;
     RECT  0.061 13.8 0.173 13.872 ;
     RECT  0.084 13.872 0.173 13.896 ;
     RECT  0.061 13.896 0.173 13.968 ;
     RECT  0.084 13.968 0.173 13.992 ;
     RECT  0.061 13.992 0.173 14.064 ;
     RECT  0.084 14.064 0.173 14.088 ;
     RECT  0.061 14.088 0.173 14.16 ;
     RECT  0.084 14.16 0.173 14.184 ;
     RECT  0.061 14.184 0.173 14.256 ;
     RECT  0.084 14.256 0.173 14.28 ;
     RECT  0.061 14.28 0.173 14.352 ;
     RECT  0.084 14.352 0.173 14.376 ;
     RECT  0.061 14.376 0.173 14.448 ;
     RECT  0.084 14.448 0.173 14.472 ;
     RECT  0.061 14.472 0.173 14.544 ;
     RECT  0.084 14.544 0.173 14.568 ;
     RECT  0.061 14.568 0.173 14.64 ;
     RECT  0.084 14.64 0.173 14.664 ;
     RECT  0.061 14.664 0.173 14.736 ;
     RECT  0.084 14.736 0.173 14.76 ;
     RECT  0.061 14.76 0.173 14.832 ;
     RECT  0.084 14.832 0.173 14.856 ;
     RECT  0.061 14.856 0.173 14.928 ;
     RECT  0.084 14.928 0.173 14.952 ;
     RECT  0.061 14.952 0.173 15.024 ;
     RECT  0.084 15.024 0.173 15.048 ;
     RECT  0.061 15.048 0.173 15.12 ;
     RECT  0.084 15.12 0.173 15.144 ;
     RECT  0.061 15.144 0.173 15.216 ;
     RECT  0.084 15.216 0.173 15.24 ;
     RECT  0.061 15.24 0.173 15.312 ;
     RECT  0.084 15.312 0.173 15.336 ;
     RECT  0.061 15.336 0.173 15.408 ;
     RECT  0.084 15.408 0.173 15.432 ;
     RECT  0.061 15.432 0.173 15.504 ;
     RECT  0.084 15.504 0.173 15.528 ;
     RECT  0.061 15.528 0.173 15.6 ;
     RECT  0.084 15.6 0.173 15.624 ;
     RECT  0.061 15.624 0.173 15.696 ;
     RECT  0.084 15.696 0.173 15.72 ;
     RECT  0.061 15.72 0.173 15.792 ;
     RECT  0.084 15.792 0.173 15.816 ;
     RECT  0.061 15.816 0.173 15.888 ;
     RECT  0.084 15.888 0.173 15.912 ;
     RECT  0.061 15.912 0.173 15.984 ;
     RECT  0.084 15.984 0.173 16.008 ;
     RECT  0.061 16.008 0.173 16.08 ;
     RECT  0.084 16.08 0.173 16.104 ;
     RECT  0.061 16.104 0.173 16.176 ;
     RECT  0.084 16.176 0.173 16.2 ;
     RECT  0.061 16.2 0.173 16.272 ;
     RECT  0.084 16.272 0.173 16.296 ;
     RECT  0.061 16.296 0.173 16.368 ;
     RECT  0.084 16.368 0.173 16.392 ;
     RECT  0.061 16.392 0.173 16.464 ;
     RECT  0.084 16.464 0.173 16.488 ;
     RECT  0.061 16.488 0.173 16.56 ;
     RECT  0.084 16.56 0.173 16.584 ;
     RECT  0.061 16.584 0.173 16.656 ;
     RECT  0.084 16.656 0.173 16.68 ;
     RECT  0.061 16.68 0.173 16.752 ;
     RECT  0.084 16.752 0.173 16.776 ;
     RECT  0.061 16.776 0.173 16.848 ;
     RECT  0.084 16.848 0.173 16.872 ;
     RECT  0.061 16.872 0.173 16.944 ;
     RECT  0.084 16.944 0.173 16.968 ;
     RECT  0.061 16.968 0.173 17.04 ;
     RECT  0.084 17.04 0.173 17.064 ;
     RECT  0.061 17.064 0.173 17.136 ;
     RECT  0.084 17.136 0.173 17.16 ;
     RECT  0.061 17.16 0.173 17.232 ;
     RECT  0.084 17.232 0.173 17.256 ;
     RECT  0.061 17.256 0.173 17.328 ;
     RECT  0.084 17.328 0.173 17.352 ;
     RECT  0.061 17.352 0.173 17.424 ;
     RECT  0.084 17.424 0.173 17.448 ;
     RECT  0.061 17.448 0.173 17.52 ;
     RECT  0.084 17.52 0.173 17.544 ;
     RECT  0.061 17.544 0.173 17.616 ;
     RECT  0.084 17.616 0.173 17.64 ;
     RECT  0.061 17.64 0.173 17.712 ;
     RECT  0.084 17.712 0.173 17.736 ;
     RECT  0.061 17.736 0.173 17.808 ;
     RECT  0.084 17.808 0.173 17.832 ;
     RECT  0.061 17.832 0.173 17.904 ;
     RECT  0.084 17.904 0.173 17.928 ;
     RECT  0.061 17.928 0.173 18 ;
     RECT  0.084 18 0.173 18.024 ;
     RECT  0.061 18.024 0.173 18.096 ;
     RECT  0.084 18.096 0.173 18.12 ;
     RECT  0.061 18.12 0.173 18.192 ;
     RECT  0.084 18.192 0.173 18.216 ;
     RECT  0.061 18.216 0.173 18.288 ;
     RECT  0.084 18.288 0.173 18.312 ;
     RECT  0.061 18.312 0.173 18.384 ;
     RECT  0.084 18.384 0.173 18.408 ;
     RECT  0.061 18.408 0.173 18.48 ;
     RECT  0.084 18.48 0.173 18.504 ;
     RECT  0.061 18.504 0.173 18.576 ;
     RECT  0.084 18.576 0.173 18.6 ;
     RECT  0.061 18.6 0.173 18.672 ;
     RECT  0.084 18.672 0.173 18.696 ;
     RECT  0.061 18.696 0.173 18.768 ;
     RECT  0.084 18.768 0.173 18.792 ;
     RECT  0.061 18.792 0.173 18.864 ;
     RECT  0.084 18.864 0.173 18.888 ;
     RECT  0.061 18.888 0.173 18.96 ;
     RECT  0.084 18.96 0.173 18.984 ;
     RECT  0.061 18.984 0.173 19.056 ;
     RECT  0.084 19.056 0.173 19.08 ;
     RECT  0.061 19.08 0.173 19.152 ;
     RECT  0.084 19.152 0.173 19.176 ;
     RECT  0.061 19.176 0.173 19.248 ;
     RECT  0.084 19.248 0.173 19.272 ;
     RECT  0.061 19.272 0.173 19.344 ;
     RECT  0.084 19.344 0.173 19.368 ;
     RECT  0.061 19.368 0.173 19.44 ;
     RECT  0.084 19.44 0.173 19.464 ;
     RECT  0.061 19.464 0.173 19.536 ;
     RECT  0.084 19.536 0.173 19.56 ;
     RECT  0.061 19.56 0.173 19.632 ;
     RECT  0.084 19.632 0.173 19.656 ;
     RECT  0.061 19.656 0.173 19.728 ;
     RECT  0.084 19.728 0.173 19.752 ;
     RECT  0.061 19.752 0.173 19.824 ;
     RECT  0.084 19.824 0.173 19.848 ;
     RECT  0.061 19.848 0.173 19.92 ;
     RECT  0.084 19.92 0.173 19.944 ;
     RECT  0.061 19.944 0.173 20.016 ;
     RECT  0.084 20.016 0.173 20.04 ;
     RECT  0.061 20.04 0.173 20.112 ;
     RECT  0.084 20.112 0.173 20.136 ;
     RECT  0.061 20.136 0.173 20.208 ;
     RECT  0.084 20.208 0.173 20.232 ;
     RECT  0.061 20.232 0.173 20.304 ;
     RECT  0.084 20.304 0.173 20.328 ;
     RECT  0.061 20.328 0.173 20.4 ;
     RECT  0.084 20.4 0.173 20.424 ;
     RECT  0.061 20.424 0.173 20.496 ;
     RECT  0.084 20.496 0.173 20.52 ;
     RECT  0.061 20.52 0.173 20.592 ;
     RECT  0.084 20.592 0.173 20.616 ;
     RECT  0.061 20.616 0.173 20.688 ;
     RECT  0.084 20.688 0.173 20.712 ;
     RECT  0.061 20.712 0.173 20.784 ;
     RECT  0.084 20.784 0.173 20.808 ;
     RECT  0.061 20.808 0.173 20.88 ;
     RECT  0.084 20.88 0.173 20.904 ;
     RECT  0.061 20.904 0.173 20.976 ;
     RECT  0.084 20.976 0.173 21 ;
     RECT  0.061 21 0.173 21.072 ;
     RECT  0.084 21.072 0.173 21.096 ;
     RECT  0.061 21.096 0.173 21.168 ;
     RECT  0.084 21.168 0.173 21.192 ;
     RECT  0.061 21.192 0.173 21.264 ;
     RECT  0.084 21.264 0.173 21.288 ;
     RECT  0.061 21.288 0.173 21.36 ;
     RECT  0.084 21.36 0.173 21.384 ;
     RECT  0.061 21.384 0.173 21.456 ;
     RECT  0.084 21.456 0.173 21.48 ;
     RECT  0.061 21.48 0.173 21.552 ;
     RECT  0.084 21.552 0.173 21.576 ;
     RECT  0.061 21.576 0.173 21.648 ;
     RECT  0.084 21.648 0.173 21.672 ;
     RECT  0.061 21.672 0.173 21.744 ;
     RECT  0.084 21.744 0.173 21.768 ;
     RECT  0.061 21.768 0.173 21.84 ;
     RECT  0.084 21.84 0.173 21.864 ;
     RECT  0.061 21.864 0.173 21.936 ;
     RECT  0.084 21.936 0.173 21.96 ;
     RECT  0.061 21.96 0.173 22.032 ;
     RECT  0.084 22.032 0.173 22.056 ;
     RECT  0.061 22.056 0.173 22.128 ;
     RECT  0.084 22.128 0.173 22.152 ;
     RECT  0.061 22.152 0.173 22.224 ;
     RECT  0.084 22.224 0.173 22.248 ;
     RECT  0.061 22.248 0.173 22.32 ;
     RECT  0.084 22.32 0.173 22.344 ;
     RECT  0.061 22.344 0.173 22.416 ;
     RECT  0.084 22.416 0.173 22.44 ;
     RECT  0.061 22.44 0.173 22.512 ;
     RECT  0.084 22.512 0.173 22.536 ;
     RECT  0.061 22.536 0.173 22.608 ;
     RECT  0.084 22.608 0.173 22.632 ;
     RECT  0.061 22.632 0.173 22.704 ;
     RECT  0.084 22.704 0.173 22.728 ;
     RECT  0.061 22.728 0.173 22.8 ;
     RECT  0.084 22.8 0.173 22.824 ;
     RECT  0.061 22.824 0.173 22.896 ;
     RECT  0.084 22.896 0.173 22.92 ;
     RECT  0.061 22.92 0.173 22.992 ;
     RECT  0.084 22.992 0.173 23.016 ;
     RECT  0.061 23.016 0.173 23.088 ;
     RECT  0.084 23.088 0.173 23.112 ;
     RECT  0.061 23.112 0.173 23.184 ;
     RECT  0.084 23.184 0.173 23.208 ;
     RECT  0.061 23.208 0.173 23.28 ;
     RECT  0.084 23.28 0.173 23.304 ;
     RECT  0.061 23.304 0.173 23.376 ;
     RECT  0.084 23.376 0.173 23.4 ;
     RECT  0.061 23.4 0.173 23.472 ;
     RECT  0.084 23.472 0.173 23.496 ;
     RECT  0.061 23.496 0.173 23.568 ;
     RECT  0.084 23.568 0.173 23.592 ;
     RECT  0.061 23.592 0.173 23.664 ;
     RECT  0.084 23.664 0.173 23.688 ;
     RECT  0.061 23.688 0.173 23.76 ;
     RECT  0.084 23.76 0.173 23.784 ;
     RECT  0.061 23.784 0.173 23.856 ;
     RECT  0.084 23.856 0.173 23.88 ;
     RECT  0.061 23.88 0.173 23.952 ;
     RECT  0.084 23.952 0.173 23.976 ;
     RECT  0.061 23.976 0.173 24.048 ;
     RECT  0.084 24.048 0.173 24.072 ;
     RECT  0.061 24.072 0.173 24.144 ;
     RECT  0.084 24.144 0.173 24.168 ;
     RECT  0.061 24.168 0.173 24.24 ;
     RECT  0.084 24.24 0.173 24.264 ;
     RECT  0.061 24.264 0.173 24.336 ;
     RECT  0.084 24.336 0.173 24.36 ;
     RECT  0.061 24.36 0.173 24.432 ;
     RECT  0.084 24.432 0.173 24.456 ;
     RECT  0.061 24.456 0.173 24.528 ;
     RECT  0.084 24.528 0.173 24.552 ;
     RECT  0.061 24.552 0.173 24.624 ;
     RECT  0.084 24.624 0.173 24.648 ;
     RECT  0.061 24.648 0.173 24.72 ;
     RECT  0.084 24.72 0.173 24.744 ;
     RECT  0.061 24.744 0.173 24.816 ;
     RECT  0.084 24.816 0.173 24.84 ;
     RECT  0.061 24.84 0.173 24.912 ;
     RECT  0.084 24.912 0.173 24.936 ;
     RECT  0.061 24.936 0.173 25.008 ;
     RECT  0.084 25.008 0.173 25.032 ;
     RECT  0.061 25.032 0.173 25.104 ;
     RECT  0.084 25.104 0.173 25.128 ;
     RECT  0.061 25.128 0.173 25.2 ;
     RECT  0.084 25.2 0.173 25.224 ;
     RECT  0.061 25.224 0.173 25.296 ;
     RECT  0.084 25.296 0.173 25.32 ;
     RECT  0.061 25.32 0.173 25.392 ;
     RECT  0.084 25.392 0.173 25.416 ;
     RECT  0.061 25.416 0.173 25.488 ;
     RECT  0.084 25.488 0.173 25.512 ;
     RECT  0.173 13.392 0.533 25.512 ;
     RECT  0.533 13.488 2.408 25.512 ;
     RECT  0.137 27.792 2.408 28.584 ;
     RECT  2.408 2.148 2.512 30.252 ;
     RECT  2.512 2.418 2.704 29.982 ;
     RECT  2.704 27.888 2.873 28.92 ;
     RECT  2.873 28.176 3.292 28.92 ;
     RECT  4.993 11.952 5.108 11.976 ;
     RECT  2.704 13.44 5.108 25.512 ;
     RECT  3.292 28.176 5.108 28.296 ;
     RECT  5.108 2.148 5.212 30.252 ;
     RECT  5.212 2.418 5.404 29.982 ;
     RECT  5.404 13.44 6.829 25.512 ;
     RECT  5.404 11.952 7.808 11.976 ;
     RECT  6.829 13.344 7.808 25.512 ;
     RECT  5.404 28.176 7.808 28.296 ;
     RECT  7.808 2.148 7.912 30.252 ;
     RECT  7.912 2.418 8.104 29.982 ;
     RECT  10.309 4.656 10.508 4.68 ;
     RECT  8.104 11.952 10.508 11.976 ;
     RECT  8.104 13.344 10.508 25.512 ;
     RECT  8.104 28.176 10.508 28.296 ;
     RECT  10.508 2.148 10.612 30.252 ;
     RECT  10.612 2.418 10.804 29.982 ;
     RECT  10.804 13.344 11.369 25.032 ;
     RECT  11.369 13.344 11.405 15.048 ;
     RECT  11.369 16.272 11.405 25.032 ;
     RECT  11.405 16.368 11.441 16.536 ;
     RECT  10.804 28.176 11.699 28.296 ;
     RECT  11.405 13.344 11.945 15 ;
     RECT  10.804 11.952 12.049 11.976 ;
     RECT  11.945 13.344 12.049 14.856 ;
     RECT  10.804 4.656 12.121 4.68 ;
     RECT  12.049 11.952 12.193 14.856 ;
     RECT  12.193 11.376 12.661 14.856 ;
     RECT  11.441 16.512 12.853 16.536 ;
     RECT  11.405 17.664 12.853 21.48 ;
     RECT  12.517 7.872 13.052 7.896 ;
     RECT  12.877 9.552 13.052 9.576 ;
     RECT  12.853 16.512 13.201 21.48 ;
     RECT  12.121 4.512 13.208 4.68 ;
     RECT  13.052 7.872 13.208 9.576 ;
     RECT  12.661 10.8 13.208 14.856 ;
     RECT  13.201 15.984 13.208 21.48 ;
     RECT  11.405 23.952 13.208 25.032 ;
     RECT  11.699 28.272 13.208 28.296 ;
     RECT  13.208 2.148 13.312 30.252 ;
     RECT  13.312 2.418 13.504 29.982 ;
     RECT  13.504 23.952 13.565 25.032 ;
     RECT  13.504 7.344 13.709 14.52 ;
     RECT  13.709 7.344 13.811 13.848 ;
     RECT  13.504 4.56 13.889 5.112 ;
     RECT  13.811 7.872 14.821 13.848 ;
     RECT  13.889 4.56 14.857 4.776 ;
     RECT  14.821 7.392 14.857 13.848 ;
     RECT  13.504 15.504 14.893 21.48 ;
     RECT  14.857 7.392 14.933 14.136 ;
     RECT  14.933 8.496 15.541 14.136 ;
     RECT  14.893 15.216 15.541 21.48 ;
     RECT  14.857 4.56 15.613 5.016 ;
     RECT  15.613 4.512 15.721 5.016 ;
     RECT  14.933 7.392 15.781 7.416 ;
     RECT  15.781 7.2 15.865 7.416 ;
     RECT  15.721 4.272 15.908 5.016 ;
     RECT  15.865 6.816 15.908 7.416 ;
     RECT  15.541 8.496 15.908 21.48 ;
     RECT  13.565 24.912 15.908 25.032 ;
     RECT  15.908 2.148 16.012 30.252 ;
     RECT  16.012 2.418 16.204 29.982 ;
     RECT  16.204 24.912 16.697 24.936 ;
     RECT  16.204 4.512 16.732 4.776 ;
     RECT  16.204 9.072 16.985 19.848 ;
     RECT  16.204 20.976 17.021 21.48 ;
     RECT  16.985 9.072 17.129 14.28 ;
     RECT  17.129 9.216 17.309 14.28 ;
     RECT  17.021 20.976 17.453 21.432 ;
     RECT  16.204 6.816 17.489 7.944 ;
     RECT  16.732 4.512 17.561 4.68 ;
     RECT  16.985 15.504 17.561 19.848 ;
     RECT  17.309 9.216 18.205 13.416 ;
     RECT  17.561 4.656 18.608 4.68 ;
     RECT  17.489 7.632 18.608 7.944 ;
     RECT  18.205 9.072 18.608 13.416 ;
     RECT  17.561 15.504 18.608 19.416 ;
     RECT  17.453 20.976 18.608 21 ;
     RECT  18.608 2.148 18.712 30.252 ;
     RECT  18.712 2.418 18.904 29.982 ;
     RECT  18.904 3.984 19.897 4.68 ;
     RECT  18.904 7.344 19.897 19.08 ;
     RECT  19.897 7.056 20.509 19.08 ;
     RECT  19.897 3.792 21.516 3.816 ;
     RECT  19.897 3.816 21.564 3.888 ;
     RECT  19.897 3.888 21.516 3.912 ;
     RECT  19.897 3.912 21.564 3.984 ;
     RECT  19.897 3.984 21.516 4.008 ;
     RECT  19.897 4.008 21.564 4.08 ;
     RECT  19.897 4.08 21.516 4.104 ;
     RECT  19.897 4.104 21.564 4.176 ;
     RECT  19.897 4.176 21.516 4.2 ;
     RECT  19.897 4.2 21.564 4.272 ;
     RECT  19.897 4.272 21.516 4.296 ;
     RECT  19.897 4.296 21.564 4.368 ;
     RECT  19.897 4.368 21.516 4.392 ;
     RECT  19.897 4.392 21.564 4.464 ;
     RECT  19.897 4.464 21.516 4.488 ;
     RECT  19.897 4.488 21.564 4.56 ;
     RECT  19.897 4.56 21.516 4.584 ;
     RECT  19.897 4.584 21.564 4.656 ;
     RECT  19.897 4.656 21.516 4.68 ;
     RECT  20.509 6.864 21.516 6.888 ;
     RECT  20.509 6.888 21.564 6.96 ;
     RECT  20.509 6.96 21.516 6.984 ;
     RECT  20.509 6.984 21.564 7.056 ;
     RECT  20.509 7.056 21.516 7.08 ;
     RECT  20.509 7.08 21.564 7.152 ;
     RECT  20.509 7.152 21.516 7.176 ;
     RECT  20.509 7.176 21.564 7.248 ;
     RECT  20.509 7.248 21.516 7.272 ;
     RECT  20.509 7.272 21.564 7.344 ;
     RECT  20.509 7.344 21.516 7.368 ;
     RECT  20.509 7.368 21.564 7.44 ;
     RECT  20.509 7.44 21.516 7.464 ;
     RECT  20.509 7.464 21.564 7.536 ;
     RECT  20.509 7.536 21.516 7.56 ;
     RECT  20.509 7.56 21.564 7.632 ;
     RECT  20.509 7.632 21.516 7.656 ;
     RECT  20.509 7.656 21.564 7.728 ;
     RECT  20.509 7.728 21.516 7.752 ;
     RECT  20.509 7.752 21.564 7.824 ;
     RECT  20.509 7.824 21.516 7.848 ;
     RECT  20.509 7.848 21.564 7.92 ;
     RECT  20.509 7.92 21.516 7.944 ;
     RECT  20.509 7.944 21.564 8.016 ;
     RECT  20.509 8.016 21.516 8.04 ;
     RECT  20.509 8.04 21.564 8.112 ;
     RECT  20.509 8.112 21.516 8.136 ;
     RECT  20.509 8.136 21.564 8.208 ;
     RECT  20.509 8.208 21.516 8.232 ;
     RECT  20.509 8.232 21.564 8.304 ;
     RECT  20.509 8.304 21.516 8.328 ;
     RECT  20.509 8.328 21.564 8.4 ;
     RECT  20.509 8.4 21.516 8.424 ;
     RECT  20.509 8.424 21.564 8.496 ;
     RECT  20.509 8.496 21.516 8.52 ;
     RECT  20.509 8.52 21.564 8.592 ;
     RECT  20.509 8.592 21.516 8.616 ;
     RECT  20.509 8.616 21.564 8.688 ;
     RECT  20.509 8.688 21.516 8.712 ;
     RECT  20.509 8.712 21.564 8.784 ;
     RECT  20.509 8.784 21.516 8.808 ;
     RECT  20.509 8.808 21.564 8.88 ;
     RECT  20.509 8.88 21.516 8.904 ;
     RECT  20.509 8.904 21.564 8.976 ;
     RECT  20.509 8.976 21.516 9 ;
     RECT  20.509 9 21.564 9.072 ;
     RECT  20.509 9.072 21.516 9.096 ;
     RECT  20.509 9.096 21.564 9.168 ;
     RECT  20.509 9.168 21.516 9.192 ;
     RECT  20.509 9.192 21.564 9.264 ;
     RECT  20.509 9.264 21.516 9.288 ;
     RECT  20.509 9.288 21.564 9.36 ;
     RECT  20.509 9.36 21.516 9.384 ;
     RECT  20.509 9.384 21.564 9.456 ;
     RECT  20.509 9.456 21.516 9.48 ;
     RECT  20.509 9.48 21.564 9.552 ;
     RECT  20.509 9.552 21.516 9.576 ;
     RECT  20.509 9.576 21.564 9.648 ;
     RECT  20.509 9.648 21.516 9.672 ;
     RECT  20.509 9.672 21.564 9.744 ;
     RECT  20.509 9.744 21.516 9.768 ;
     RECT  20.509 9.768 21.564 9.84 ;
     RECT  20.509 9.84 21.516 9.864 ;
     RECT  20.509 9.864 21.564 9.936 ;
     RECT  20.509 9.936 21.516 9.96 ;
     RECT  20.509 9.96 21.564 10.032 ;
     RECT  20.509 10.032 21.516 10.056 ;
     RECT  20.509 10.056 21.564 10.128 ;
     RECT  20.509 10.128 21.516 10.152 ;
     RECT  20.509 10.152 21.564 10.224 ;
     RECT  20.509 10.224 21.516 10.248 ;
     RECT  20.509 10.248 21.564 10.32 ;
     RECT  20.509 10.32 21.516 10.344 ;
     RECT  20.509 10.344 21.564 10.416 ;
     RECT  20.509 10.416 21.516 10.44 ;
     RECT  20.509 10.44 21.564 10.512 ;
     RECT  20.509 10.512 21.516 10.536 ;
     RECT  20.509 10.536 21.564 10.608 ;
     RECT  20.509 10.608 21.516 10.632 ;
     RECT  20.509 10.632 21.564 10.704 ;
     RECT  20.509 10.704 21.516 10.728 ;
     RECT  20.509 10.728 21.564 10.8 ;
     RECT  20.509 10.8 21.516 10.824 ;
     RECT  20.509 10.824 21.564 10.896 ;
     RECT  20.509 10.896 21.516 10.92 ;
     RECT  20.509 10.92 21.564 10.992 ;
     RECT  20.509 10.992 21.516 11.016 ;
     RECT  20.509 11.016 21.564 11.088 ;
     RECT  20.509 11.088 21.516 11.112 ;
     RECT  20.509 11.112 21.564 11.184 ;
     RECT  20.509 11.184 21.516 11.208 ;
     RECT  20.509 11.208 21.564 11.28 ;
     RECT  20.509 11.28 21.516 11.304 ;
     RECT  20.509 11.304 21.564 11.376 ;
     RECT  20.509 11.376 21.516 11.4 ;
     RECT  20.509 11.4 21.564 11.472 ;
     RECT  20.509 11.472 21.516 11.496 ;
     RECT  20.509 11.496 21.564 11.568 ;
     RECT  20.509 11.568 21.516 11.592 ;
     RECT  20.509 11.592 21.564 11.664 ;
     RECT  20.509 11.664 21.516 11.688 ;
     RECT  20.509 11.688 21.564 11.76 ;
     RECT  20.509 11.76 21.516 11.784 ;
     RECT  20.509 11.784 21.564 11.856 ;
     RECT  20.509 11.856 21.516 11.88 ;
     RECT  20.509 11.88 21.564 11.952 ;
     RECT  20.509 11.952 21.516 11.976 ;
     RECT  20.509 11.976 21.564 12.048 ;
     RECT  20.509 12.048 21.516 12.072 ;
     RECT  20.509 12.072 21.564 12.144 ;
     RECT  20.509 12.144 21.516 12.168 ;
     RECT  20.509 12.168 21.564 12.24 ;
     RECT  20.509 12.24 21.516 12.264 ;
     RECT  20.509 12.264 21.564 12.336 ;
     RECT  20.509 12.336 21.516 12.36 ;
     RECT  20.509 12.36 21.564 12.432 ;
     RECT  20.509 12.432 21.516 12.456 ;
     RECT  20.509 12.456 21.564 12.528 ;
     RECT  20.509 12.528 21.516 12.552 ;
     RECT  20.509 12.552 21.564 12.624 ;
     RECT  20.509 12.624 21.516 12.648 ;
     RECT  20.509 12.648 21.564 12.72 ;
     RECT  20.509 12.72 21.516 12.744 ;
     RECT  20.509 12.744 21.564 12.816 ;
     RECT  20.509 12.816 21.516 12.84 ;
     RECT  20.509 12.84 21.564 12.912 ;
     RECT  20.509 12.912 21.516 12.936 ;
     RECT  20.509 12.936 21.564 13.008 ;
     RECT  20.509 13.008 21.516 13.032 ;
     RECT  20.509 13.032 21.564 13.104 ;
     RECT  20.509 13.104 21.516 13.128 ;
     RECT  20.509 13.128 21.564 13.2 ;
     RECT  20.509 13.2 21.516 13.224 ;
     RECT  20.509 13.224 21.564 13.296 ;
     RECT  20.509 13.296 21.516 13.32 ;
     RECT  20.509 13.32 21.564 13.392 ;
     RECT  20.509 13.392 21.516 13.416 ;
     RECT  20.509 13.416 21.564 13.488 ;
     RECT  20.509 13.488 21.516 13.512 ;
     RECT  20.509 13.512 21.564 13.584 ;
     RECT  20.509 13.584 21.516 13.608 ;
     RECT  20.509 13.608 21.564 13.68 ;
     RECT  20.509 13.68 21.516 13.704 ;
     RECT  20.509 13.704 21.564 13.776 ;
     RECT  20.509 13.776 21.516 13.8 ;
     RECT  20.509 13.8 21.564 13.872 ;
     RECT  20.509 13.872 21.516 13.896 ;
     RECT  20.509 13.896 21.564 13.968 ;
     RECT  20.509 13.968 21.516 13.992 ;
     RECT  20.509 13.992 21.564 14.064 ;
     RECT  20.509 14.064 21.516 14.088 ;
     RECT  20.509 14.088 21.564 14.16 ;
     RECT  20.509 14.16 21.516 14.184 ;
     RECT  20.509 14.184 21.564 14.256 ;
     RECT  20.509 14.256 21.516 14.28 ;
     RECT  20.509 14.28 21.564 14.352 ;
     RECT  20.509 14.352 21.516 14.376 ;
     RECT  20.509 14.376 21.564 14.448 ;
     RECT  20.509 14.448 21.516 14.472 ;
     RECT  20.509 14.472 21.564 14.544 ;
     RECT  20.509 14.544 21.516 14.568 ;
     RECT  20.509 14.568 21.564 14.64 ;
     RECT  20.509 14.64 21.516 14.664 ;
     RECT  20.509 14.664 21.564 14.736 ;
     RECT  20.509 14.736 21.516 14.76 ;
     RECT  20.509 14.76 21.564 14.832 ;
     RECT  20.509 14.832 21.516 14.856 ;
     RECT  20.509 14.856 21.564 14.928 ;
     RECT  20.509 14.928 21.516 14.952 ;
     RECT  20.509 14.952 21.564 15.024 ;
     RECT  20.509 15.024 21.516 15.048 ;
     RECT  20.509 15.048 21.564 15.12 ;
     RECT  20.509 15.12 21.516 15.144 ;
     RECT  20.509 15.144 21.564 15.216 ;
     RECT  20.509 15.216 21.516 15.24 ;
     RECT  20.509 15.24 21.564 15.312 ;
     RECT  20.509 15.312 21.516 15.336 ;
     RECT  20.509 15.336 21.564 15.408 ;
     RECT  20.509 15.408 21.516 15.432 ;
     RECT  20.509 15.432 21.564 15.504 ;
     RECT  20.509 15.504 21.516 15.528 ;
     RECT  20.509 15.528 21.564 15.6 ;
     RECT  20.509 15.6 21.516 15.624 ;
     RECT  20.509 15.624 21.564 15.696 ;
     RECT  20.509 15.696 21.516 15.72 ;
     RECT  20.509 15.72 21.564 15.792 ;
     RECT  20.509 15.792 21.516 15.816 ;
     RECT  20.509 15.816 21.564 15.888 ;
     RECT  20.509 15.888 21.516 15.912 ;
     RECT  20.509 15.912 21.564 15.984 ;
     RECT  20.509 15.984 21.516 16.008 ;
     RECT  20.509 16.008 21.564 16.08 ;
     RECT  20.509 16.08 21.516 16.104 ;
     RECT  20.509 16.104 21.564 16.176 ;
     RECT  20.509 16.176 21.516 16.2 ;
     RECT  20.509 16.2 21.564 16.272 ;
     RECT  20.509 16.272 21.516 16.296 ;
     RECT  20.509 16.296 21.564 16.368 ;
     RECT  20.509 16.368 21.516 16.392 ;
     RECT  20.509 16.392 21.564 16.464 ;
     RECT  20.509 16.464 21.516 16.488 ;
     RECT  20.509 16.488 21.564 16.56 ;
     RECT  20.509 16.56 21.516 16.584 ;
     RECT  20.509 16.584 21.564 16.656 ;
     RECT  20.509 16.656 21.516 16.68 ;
     RECT  20.509 16.68 21.564 16.752 ;
     RECT  20.509 16.752 21.516 16.776 ;
     RECT  20.509 16.776 21.564 16.848 ;
     RECT  20.509 16.848 21.516 16.872 ;
     RECT  20.509 16.872 21.564 16.944 ;
     RECT  20.509 16.944 21.516 16.968 ;
     RECT  20.509 16.968 21.564 17.04 ;
     RECT  20.509 17.04 21.516 17.064 ;
     RECT  20.509 17.064 21.564 17.136 ;
     RECT  20.509 17.136 21.516 17.16 ;
     RECT  20.509 17.16 21.564 17.232 ;
     RECT  20.509 17.232 21.516 17.256 ;
     RECT  20.509 17.256 21.564 17.328 ;
     RECT  20.509 17.328 21.516 17.352 ;
     RECT  20.509 17.352 21.564 17.424 ;
     RECT  20.509 17.424 21.516 17.448 ;
     RECT  20.509 17.448 21.564 17.52 ;
     RECT  20.509 17.52 21.516 17.544 ;
     RECT  20.509 17.544 21.564 17.616 ;
     RECT  20.509 17.616 21.516 17.64 ;
     RECT  20.509 17.64 21.564 17.712 ;
     RECT  20.509 17.712 21.516 17.736 ;
     RECT  20.509 17.736 21.564 17.808 ;
     RECT  20.509 17.808 21.516 17.832 ;
     RECT  20.509 17.832 21.564 17.904 ;
     RECT  20.509 17.904 21.516 17.928 ;
     RECT  20.509 17.928 21.564 18 ;
     RECT  20.509 18 21.516 18.024 ;
     RECT  20.509 18.024 21.564 18.096 ;
     RECT  20.509 18.096 21.516 18.12 ;
     RECT  20.509 18.12 21.564 18.192 ;
     RECT  20.509 18.192 21.516 18.216 ;
     RECT  20.509 18.216 21.564 18.288 ;
     RECT  20.509 18.288 21.516 18.312 ;
     RECT  20.509 18.312 21.564 18.384 ;
     RECT  20.509 18.384 21.516 18.408 ;
     RECT  20.509 18.408 21.564 18.48 ;
     RECT  20.509 18.48 21.516 18.504 ;
     RECT  20.509 18.504 21.564 18.576 ;
     RECT  20.509 18.576 21.516 18.6 ;
     RECT  20.509 18.6 21.564 18.672 ;
     RECT  20.509 18.672 21.516 18.696 ;
     RECT  20.509 18.696 21.564 18.768 ;
     RECT  20.509 18.768 21.516 18.792 ;
     RECT  20.509 18.792 21.564 18.864 ;
     RECT  20.509 18.864 21.516 18.888 ;
     RECT  20.509 18.888 21.564 18.96 ;
     RECT  20.509 18.96 21.516 18.984 ;
     RECT  20.509 18.984 21.564 19.056 ;
     RECT  20.509 19.056 21.516 19.08 ;
    LAYER M5 ;
     RECT  2.4 2.137 2.52 2.151 ;
     RECT  5.1 2.137 5.22 2.151 ;
     RECT  7.8 2.137 7.92 2.151 ;
     RECT  10.5 2.137 10.62 2.151 ;
     RECT  13.2 2.137 13.32 2.151 ;
     RECT  15.9 2.137 16.02 2.151 ;
     RECT  18.6 2.137 18.72 2.151 ;
     RECT  15.9 2.151 16.212 4.261 ;
     RECT  13.2 2.151 13.512 4.501 ;
     RECT  10.5 2.151 10.812 4.645 ;
     RECT  15.792 4.261 16.212 4.741 ;
     RECT  12.528 4.501 13.512 5.077 ;
     RECT  14.832 4.741 16.68 6.851 ;
     RECT  12.528 5.077 13.8 7.379 ;
     RECT  14.832 6.851 16.212 7.861 ;
     RECT  12.528 7.379 13.512 7.907 ;
     RECT  13.104 7.907 13.512 8.675 ;
     RECT  14.736 7.861 16.212 9.685 ;
     RECT  18.6 2.151 18.912 9.685 ;
     RECT  17.664 9.685 18.912 10.259 ;
     RECT  14.592 9.685 16.212 10.307 ;
     RECT  13.2 8.675 13.512 10.789 ;
     RECT  12.768 10.789 13.512 11.365 ;
     RECT  15.168 10.307 16.212 13.141 ;
     RECT  12.672 11.365 13.512 13.189 ;
     RECT  15.168 13.141 17.112 13.427 ;
     RECT  12.672 13.189 13.608 13.619 ;
     RECT  15.168 13.427 16.212 13.667 ;
     RECT  12.672 13.619 13.512 14.867 ;
     RECT  10.32 4.645 10.812 16.211 ;
     RECT  0.144 16.021 0.168 16.307 ;
     RECT  13.2 14.867 13.512 16.501 ;
     RECT  15.552 13.667 16.212 17.509 ;
     RECT  12.864 16.501 13.512 17.651 ;
     RECT  15.552 17.509 17.016 17.651 ;
     RECT  15.9 17.651 17.016 18.085 ;
     RECT  18.6 10.259 18.912 18.085 ;
     RECT  13.008 17.651 13.512 18.709 ;
     RECT  15.9 18.085 18.912 18.851 ;
     RECT  17.664 18.851 18.912 19.427 ;
     RECT  13.008 18.709 14.136 19.955 ;
     RECT  11.952 19.093 11.976 20.003 ;
     RECT  13.008 19.955 13.512 20.003 ;
     RECT  10.5 16.211 10.812 20.437 ;
     RECT  2.4 2.151 2.712 28.165 ;
     RECT  10.5 20.437 11.688 28.211 ;
     RECT  2.4 28.165 3.24 28.931 ;
     RECT  2.4 28.931 2.712 30.249 ;
     RECT  5.1 2.151 5.412 30.249 ;
     RECT  7.8 2.151 8.112 30.249 ;
     RECT  10.5 28.211 10.812 30.249 ;
     RECT  13.2 20.003 13.512 30.249 ;
     RECT  15.9 18.851 16.212 30.249 ;
     RECT  18.6 19.427 18.912 30.249 ;
     RECT  2.4 30.249 2.52 30.263 ;
     RECT  5.1 30.249 5.22 30.263 ;
     RECT  7.8 30.249 7.92 30.263 ;
     RECT  10.5 30.249 10.62 30.263 ;
     RECT  13.2 30.249 13.32 30.263 ;
     RECT  15.9 30.249 16.02 30.263 ;
     RECT  18.6 30.249 18.72 30.263 ;
     RECT  13.512 4.741 14.832 5.077 ;
     RECT  13.8 5.077 14.832 7.379 ;
     RECT  13.512 7.379 14.832 7.861 ;
     RECT  13.512 7.861 14.736 9.685 ;
     RECT  13.512 9.685 14.592 10.307 ;
     RECT  16.212 9.685 17.664 10.259 ;
     RECT  17.112 13.141 18.6 13.427 ;
     RECT  12.864 17.651 13.008 19.093 ;
     RECT  16.212 18.851 17.664 19.427 ;
     RECT  10.812 19.093 11.952 20.003 ;
     RECT  11.976 19.093 13.008 20.003 ;
     RECT  10.812 20.003 13.2 20.437 ;
     RECT  11.688 20.437 13.2 28.211 ;
  END
END hbfd_lh_136_EW
END LIBRARY
